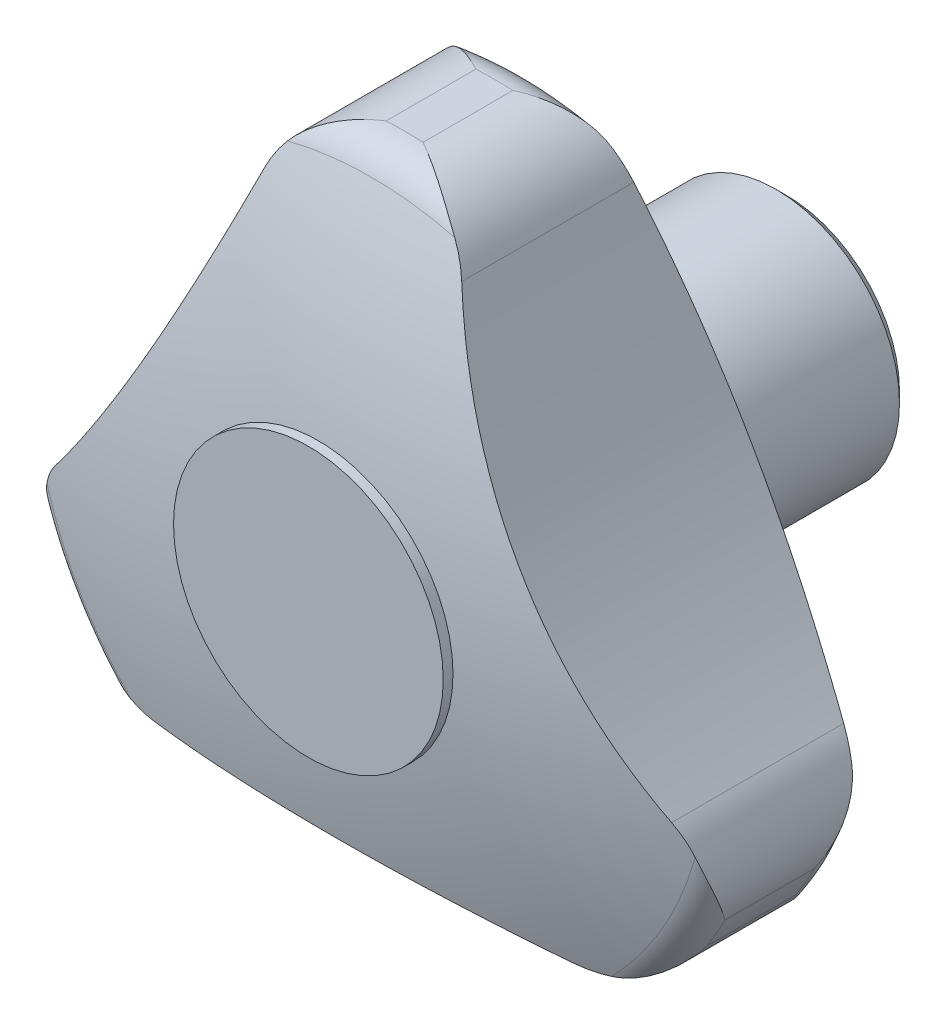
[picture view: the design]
ISO-10303-21;
HEADER;
FILE_DESCRIPTION(('STEP AP214'),'2;1');
FILE_NAME('part.step','',(''),(''),'','','');
FILE_SCHEMA(('AUTOMOTIVE_DESIGN { 1 0 10303 214 1 1 1 1 }'));
ENDSEC;
DATA;
#1=APPLICATION_CONTEXT('core data for automotive mechanical design processes');
#2=APPLICATION_PROTOCOL_DEFINITION('international standard','automotive_design',2000,#1);
#3=PRODUCT_CONTEXT('',#1,'mechanical');
#4=PRODUCT('Part','Part','',(#3));
#5=PRODUCT_RELATED_PRODUCT_CATEGORY('part','',(#4));
#6=PRODUCT_DEFINITION_FORMATION('','',#4);
#7=PRODUCT_DEFINITION_CONTEXT('part definition',#1,'design');
#8=PRODUCT_DEFINITION('design','',#6,#7);
#9=PRODUCT_DEFINITION_SHAPE('','',#8);
#10=(LENGTH_UNIT() NAMED_UNIT(*) SI_UNIT(.MILLI.,.METRE.));
#11=(NAMED_UNIT(*) PLANE_ANGLE_UNIT() SI_UNIT($,.RADIAN.));
#12=(NAMED_UNIT(*) SI_UNIT($,.STERADIAN.) SOLID_ANGLE_UNIT());
#13=UNCERTAINTY_MEASURE_WITH_UNIT(LENGTH_MEASURE(1.E-05),#10,'distance_accuracy_value','');
#14=(GEOMETRIC_REPRESENTATION_CONTEXT(3) GLOBAL_UNCERTAINTY_ASSIGNED_CONTEXT((#13)) GLOBAL_UNIT_ASSIGNED_CONTEXT((#10,
#11,#12)) REPRESENTATION_CONTEXT('',''));
#15=CARTESIAN_POINT('',(0.,0.,0.));
#16=DIRECTION('',(0.,0.,1.));
#17=DIRECTION('',(1.,0.,0.));
#18=AXIS2_PLACEMENT_3D('',#15,#16,#17);
#19=CARTESIAN_POINT('',(0.,2.77555756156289E-13,-50.4999999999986));
#20=DIRECTION('',(0.,0.,1.));
#21=DIRECTION('',(0.,-1.,0.));
#22=AXIS2_PLACEMENT_3D('',#19,#20,#21);
#23=SPHERICAL_SURFACE('',#22,103.999999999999);
#24=CARTESIAN_POINT('',(9.30341411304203,36.2662225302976,46.5268395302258));
#25=CARTESIAN_POINT('',(9.48514389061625,36.0425927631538,46.5930047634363));
#26=CARTESIAN_POINT('',(9.65680365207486,35.8115267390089,46.6615574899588));
#27=CARTESIAN_POINT('',(9.97797395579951,35.3380282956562,46.80236289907));
#28=CARTESIAN_POINT('',(10.1276303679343,35.095686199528,46.8745865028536));
#29=CARTESIAN_POINT('',(10.405333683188,34.5999848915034,47.0225936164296));
#30=CARTESIAN_POINT('',(10.5333813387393,34.346626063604,47.0983770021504));
#31=CARTESIAN_POINT('',(10.7680546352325,33.8289090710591,47.2534728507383));
#32=CARTESIAN_POINT('',(10.8745238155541,33.5644862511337,47.3328063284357));
#33=CARTESIAN_POINT('',(10.9693896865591,33.2963396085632,47.413360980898));
#34=B_SPLINE_CURVE_WITH_KNOTS('',3,(#24,#25,#26,#27,#28,#29,#30,#31,#32,#33),.UNSPECIFIED.,.F.,
.F.,(4,2,2,2,4),(0.,0.88665818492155,1.76714402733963,2.64759920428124,3.53422637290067),.UNSPECIFIED.);
#35=CARTESIAN_POINT('',(9.30396328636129,36.2655465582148,46.5270395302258));
#36=VERTEX_POINT('',#35);
#37=CARTESIAN_POINT('',(10.9693189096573,33.2965396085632,47.4133008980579));
#38=VERTEX_POINT('',#37);
#39=EDGE_CURVE('E332',#36,#38,#34,.T.);
#40=ORIENTED_EDGE('',*,*,#39,.F.);
#41=CARTESIAN_POINT('',(0.,0.,46.5270395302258));
#42=DIRECTION('',(0.,0.,1.));
#43=DIRECTION('',(1.,0.,0.));
#44=AXIS2_PLACEMENT_3D('',#41,#42,#43);
#45=CIRCLE('',#44,37.44);
#46=CARTESIAN_POINT('',(-9.30396328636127,36.2655465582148,46.5270395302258));
#47=VERTEX_POINT('',#46);
#48=EDGE_CURVE('E172',#36,#47,#45,.T.);
#49=ORIENTED_EDGE('',*,*,#48,.T.);
#50=CARTESIAN_POINT('',(-10.969389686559,33.2963396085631,47.413360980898));
#51=CARTESIAN_POINT('',(-10.8745238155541,33.5644862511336,47.3328063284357));
#52=CARTESIAN_POINT('',(-10.7680546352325,33.8289090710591,47.2534728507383));
#53=CARTESIAN_POINT('',(-10.5333813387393,34.3466260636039,47.0983770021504));
#54=CARTESIAN_POINT('',(-10.405333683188,34.5999848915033,47.0225936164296));
#55=CARTESIAN_POINT('',(-10.1276303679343,35.0956861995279,46.8745865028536));
#56=CARTESIAN_POINT('',(-9.97797395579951,35.3380282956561,46.80236289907));
#57=CARTESIAN_POINT('',(-9.65680365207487,35.8115267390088,46.6615574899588));
#58=CARTESIAN_POINT('',(-9.48514389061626,36.0425927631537,46.5930047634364));
#59=CARTESIAN_POINT('',(-9.30341411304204,36.2662225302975,46.5268395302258));
#60=B_SPLINE_CURVE_WITH_KNOTS('',3,(#50,#51,#52,#53,#54,#55,#56,#57,#58,#59),.UNSPECIFIED.,.F.,
.F.,(4,2,2,2,4),(0.,0.886627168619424,1.76708234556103,2.64756818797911,3.53422637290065),.UNSPECIFIED.);
#61=CARTESIAN_POINT('',(-10.9693189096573,33.2965396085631,47.4133008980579));
#62=VERTEX_POINT('',#61);
#63=EDGE_CURVE('E323',#62,#47,#60,.T.);
#64=ORIENTED_EDGE('',*,*,#63,.F.);
#65=CARTESIAN_POINT('',(-10.9692481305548,33.2967396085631,47.4132408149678));
#66=CARTESIAN_POINT('',(-11.2987102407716,32.365714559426,47.6929493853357));
#67=CARTESIAN_POINT('',(-11.6406264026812,31.4338839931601,47.9553752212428));
#68=CARTESIAN_POINT('',(-12.349297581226,29.5703975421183,48.4451343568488));
#69=CARTESIAN_POINT('',(-12.7160537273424,28.6387416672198,48.672466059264));
#70=CARTESIAN_POINT('',(-13.474371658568,26.7773132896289,49.0915207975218));
#71=CARTESIAN_POINT('',(-13.8659377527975,25.8475411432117,49.2832376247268));
#72=CARTESIAN_POINT('',(-14.6735500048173,23.9919094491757,49.630560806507));
#73=CARTESIAN_POINT('',(-15.0895956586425,23.0660498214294,49.7861679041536));
#74=CARTESIAN_POINT('',(-15.9340357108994,21.2453954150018,50.0571314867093));
#75=CARTESIAN_POINT('',(-16.3617783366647,20.3504451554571,50.1734749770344));
#76=CARTESIAN_POINT('',(-17.2395590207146,18.5676638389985,50.3713858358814));
#77=CARTESIAN_POINT('',(-17.6895970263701,17.6798327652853,50.4529532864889));
#78=CARTESIAN_POINT('',(-18.6112868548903,15.9130800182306,50.5811082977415));
#79=CARTESIAN_POINT('',(-19.0829350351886,15.0341568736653,50.6277017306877));
#80=CARTESIAN_POINT('',(-20.047131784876,13.2867499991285,50.6858274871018));
#81=CARTESIAN_POINT('',(-20.5396801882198,12.4182661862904,50.6973600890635));
#82=CARTESIAN_POINT('',(-22.0055533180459,9.90270393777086,50.6797950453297));
#83=CARTESIAN_POINT('',(-23.0058802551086,8.2713575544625,50.6037870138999));
#84=CARTESIAN_POINT('',(-25.073415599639,5.06278721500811,50.323382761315));
#85=CARTESIAN_POINT('',(-26.1406307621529,3.48556875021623,50.1189735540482));
#86=CARTESIAN_POINT('',(-27.7997976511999,1.14667523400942,49.7138854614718));
#87=CARTESIAN_POINT('',(-28.3704410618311,0.361452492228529,49.5597486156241));
#88=CARTESIAN_POINT('',(-29.5259023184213,-1.19127140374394,49.2184404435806));
#89=CARTESIAN_POINT('',(-30.1107204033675,-1.95877225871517,49.0312685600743));
#90=CARTESIAN_POINT('',(-31.2931215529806,-3.47489219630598,48.6243215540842));
#91=CARTESIAN_POINT('',(-31.8907031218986,-4.2235134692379,48.404550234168));
#92=CARTESIAN_POINT('',(-33.0973270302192,-5.70109012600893,47.9328719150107));
#93=CARTESIAN_POINT('',(-33.7063689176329,-6.43004628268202,47.680966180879));
#94=CARTESIAN_POINT('',(-34.3204794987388,-7.1487609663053,47.4132263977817));
#95=B_SPLINE_CURVE_WITH_KNOTS('',3,(#65,#66,#67,#68,#69,#70,#71,#72,#73,#74,#75,#76,#77,#78,#79,
#80,#81,#82,#83,#84,#85,#86,#87,#88,#89,#90,#91,#92,#93,#94),.UNSPECIFIED.,.F.,.F.,(4,2,2,2,2,2,
2,2,2,2,2,2,2,2,4),(0.,3.07914254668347,6.15842519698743,9.23824414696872,12.3179997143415,
15.313276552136,18.3085463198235,21.3033130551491,24.2980560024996,30.0367874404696,
35.7760993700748,38.7239181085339,41.6717865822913,44.6193114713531,47.5667203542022),.UNSPECIFIED.);
#96=CARTESIAN_POINT('',(-34.3203086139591,-7.14856096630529,47.4133008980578));
#97=VERTEX_POINT('',#96);
#98=EDGE_CURVE('E331',#62,#97,#95,.T.);
#99=ORIENTED_EDGE('',*,*,#98,.T.);
#100=CARTESIAN_POINT('',(-36.059177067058,-10.0761183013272,46.5268395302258));
#101=CARTESIAN_POINT('',(-35.9563713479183,-9.80691675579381,46.5930057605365));
#102=CARTESIAN_POINT('',(-35.8420902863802,-9.54271812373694,46.6615595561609));
#103=CARTESIAN_POINT('',(-35.592609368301,-9.02781990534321,46.8023671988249));
#104=CARTESIAN_POINT('',(-35.4575606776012,-8.77703914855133,46.8745919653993));
#105=CARTESIAN_POINT('',(-35.16711687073,-8.28868390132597,47.0226014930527));
#106=CARTESIAN_POINT('',(-35.0117224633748,-8.0511089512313,47.098386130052));
#107=CARTESIAN_POINT('',(-34.6806963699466,-7.58901182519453,47.2534845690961));
#108=CARTESIAN_POINT('',(-34.5049304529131,-7.36459282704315,47.3328193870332));
#109=CARTESIAN_POINT('',(-34.3201377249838,-7.14836096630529,47.413375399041));
#110=B_SPLINE_CURVE_WITH_KNOTS('',3,(#100,#101,#102,#103,#104,#105,#106,#107,#108,#109),
.UNSPECIFIED.,.F.,.F.,(4,2,2,2,4),(0.,0.886671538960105,1.76717046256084,2.64763871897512,
3.53427923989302),.UNSPECIFIED.);
#111=CARTESIAN_POINT('',(-36.0588662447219,-10.0753047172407,46.5270395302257));
#112=VERTEX_POINT('',#111);
#113=EDGE_CURVE('E22',#112,#97,#110,.T.);
#114=ORIENTED_EDGE('',*,*,#113,.F.);
#115=CARTESIAN_POINT('',(-26.7549029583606,-26.190241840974,46.5270395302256));
#116=VERTEX_POINT('',#115);
#117=EDGE_CURVE('E680',#112,#116,#45,.T.);
#118=ORIENTED_EDGE('',*,*,#117,.T.);
#119=CARTESIAN_POINT('',(-22.8551626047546,-26.0429179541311,47.5581866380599));
#120=CARTESIAN_POINT('',(-22.9372116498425,-26.0624877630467,47.5338653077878));
#121=CARTESIAN_POINT('',(-23.0195259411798,-26.081024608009,47.5096387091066));
#122=CARTESIAN_POINT('',(-23.1847449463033,-26.1160390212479,47.4613588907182));
#123=CARTESIAN_POINT('',(-23.2676502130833,-26.1325142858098,47.4373058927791));
#124=CARTESIAN_POINT('',(-23.6290737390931,-26.1995795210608,47.3332019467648));
#125=CARTESIAN_POINT('',(-23.9099819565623,-26.2394758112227,47.2542286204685));
#126=CARTESIAN_POINT('',(-24.4751156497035,-26.2952916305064,47.0992472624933));
#127=CARTESIAN_POINT('',(-24.7593430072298,-26.3111968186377,47.0232410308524));
#128=CARTESIAN_POINT('',(-25.3294885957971,-26.3186693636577,46.8746967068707));
#129=CARTESIAN_POINT('',(-25.6154086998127,-26.3102008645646,46.8021638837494));
#130=CARTESIAN_POINT('',(-26.1866152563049,-26.2686407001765,46.6612407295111));
#131=CARTESIAN_POINT('',(-26.4719013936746,-26.2355387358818,46.5928521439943));
#132=CARTESIAN_POINT('',(-27.0261408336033,-26.1468279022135,46.4639625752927));
#133=CARTESIAN_POINT('',(-27.2952262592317,-26.0923628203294,46.403241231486));
#134=CARTESIAN_POINT('',(-27.8288539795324,-25.9612040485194,46.2866189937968));
#135=CARTESIAN_POINT('',(-28.0933984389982,-25.8845212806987,46.2307157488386));
#136=CARTESIAN_POINT('',(-28.6159621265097,-25.7092780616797,46.1242125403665));
#137=CARTESIAN_POINT('',(-28.8739870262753,-25.6107374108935,46.0736078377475));
#138=CARTESIAN_POINT('',(-29.381855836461,-25.3921965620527,45.9780886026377));
#139=CARTESIAN_POINT('',(-29.6317008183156,-25.2721991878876,45.9331733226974));
#140=CARTESIAN_POINT('',(-30.0781266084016,-25.0344106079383,45.8568263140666));
#141=CARTESIAN_POINT('',(-30.2763293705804,-24.9199635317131,45.8244136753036));
#142=CARTESIAN_POINT('',(-30.6648659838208,-24.6774247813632,45.7639291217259));
#143=CARTESIAN_POINT('',(-30.8552010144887,-24.5493351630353,45.7358565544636));
#144=CARTESIAN_POINT('',(-31.227189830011,-24.2799107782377,45.6842086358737));
#145=CARTESIAN_POINT('',(-31.4088347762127,-24.1385629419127,45.6606377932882));
#146=CARTESIAN_POINT('',(-31.7623103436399,-23.8433545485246,45.6181754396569));
#147=CARTESIAN_POINT('',(-31.9341385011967,-23.689490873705,45.5992850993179));
#148=CARTESIAN_POINT('',(-32.100547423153,-23.5297170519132,45.5828146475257));
#149=B_SPLINE_CURVE_WITH_KNOTS('',3,(#119,#120,#121,#122,#123,#124,#125,#126,#127,#128,#129,
#130,#131,#132,#133,#134,#135,#136,#137,#138,#139,#140,#141,#142,#143,#144,#145,#146,#147,#148),
.UNSPECIFIED.,.F.,.F.,(4,2,2,2,2,2,2,2,2,2,2,2,2,2,4),(0.,0.263337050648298,0.526965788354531,
1.40938240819,2.29232629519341,3.17656973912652,4.06118308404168,4.90377649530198,
5.74595639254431,6.58737647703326,7.42868590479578,8.12160209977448,8.81441402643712,
9.50791624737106,10.2015917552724),.UNSPECIFIED.);
#150=CARTESIAN_POINT('',(-23.3509897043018,-26.1479786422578,47.4133008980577));
#151=VERTEX_POINT('',#150);
#152=EDGE_CURVE('E144',#151,#116,#149,.T.);
#153=ORIENTED_EDGE('',*,*,#152,.F.);
#154=CARTESIAN_POINT('',(-23.3511897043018,-26.1480157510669,47.4132432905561));
#155=CARTESIAN_POINT('',(-22.380167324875,-25.9678258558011,47.6929517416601));
#156=CARTESIAN_POINT('',(-21.4022203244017,-25.7980187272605,47.9553774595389));
#157=CARTESIAN_POINT('',(-19.4340581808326,-25.4800028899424,48.4451363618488));
#158=CARTESIAN_POINT('',(-18.4438424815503,-25.3317951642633,48.672467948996));
#159=CARTESIAN_POINT('',(-16.4526393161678,-25.0578037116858,49.0915224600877));
#160=CARTESIAN_POINT('',(-15.4516500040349,-24.9320238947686,49.2832391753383));
#161=CARTESIAN_POINT('',(-13.4408197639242,-24.7036209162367,49.6305621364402));
#162=CARTESIAN_POINT('',(-12.4309790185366,-24.6009972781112,49.786169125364));
#163=CARTESIAN_POINT('',(-10.4320260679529,-24.421976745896,50.0571325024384));
#164=CARTESIAN_POINT('',(-9.44310509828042,-24.344937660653,50.1734758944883));
#165=CARTESIAN_POINT('',(-7.46028085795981,-24.213727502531,50.3713865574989));
#166=CARTESIAN_POINT('',(-6.4663775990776,-24.159556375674,50.4529539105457));
#167=CARTESIAN_POINT('',(-4.47547994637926,-24.074386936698,50.581108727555));
#168=CARTESIAN_POINT('',(-3.47848609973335,-24.0433847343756,50.6277020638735));
#169=CARTESIAN_POINT('',(-1.4830890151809,-24.0047003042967,50.6858276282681));
#170=CARTESIAN_POINT('',(-0.484685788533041,-23.9970178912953,50.6973601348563));
#171=CARTESIAN_POINT('',(2.4267859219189,-24.0087202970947,50.6797948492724));
#172=CARTESIAN_POINT('',(4.3397311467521,-24.0593554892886,50.6037870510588));
#173=CARTESIAN_POINT('',(8.15219102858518,-24.2456076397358,50.3233840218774));
#174=CARTESIAN_POINT('',(10.0517043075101,-24.3812331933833,50.1189758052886));
#175=CARTESIAN_POINT('',(12.906820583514,-24.6486657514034,49.7138897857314));
#176=CARTESIAN_POINT('',(13.8721622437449,-24.7502455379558,49.5597537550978));
#177=CARTESIAN_POINT('',(15.7945855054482,-24.9745412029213,49.2184474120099));
#178=CARTESIAN_POINT('',(16.7516669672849,-25.0972574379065,49.031276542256));
#179=CARTESIAN_POINT('',(18.6558603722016,-25.3631854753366,48.6243317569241));
#180=CARTESIAN_POINT('',(19.6029734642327,-25.5063948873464,48.4045616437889));
#181=CARTESIAN_POINT('',(21.485898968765,-25.8125718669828,47.9328859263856));
#182=CARTESIAN_POINT('',(22.4217118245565,-25.9755386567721,47.6809815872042));
#183=CARTESIAN_POINT('',(23.3511897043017,-26.1480157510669,47.4132432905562));
#184=B_SPLINE_CURVE_WITH_KNOTS('',3,(#154,#155,#156,#157,#158,#159,#160,#161,#162,#163,#164,
#165,#166,#167,#168,#169,#170,#171,#172,#173,#174,#175,#176,#177,#178,#179,#180,#181,#182,#183),
.UNSPECIFIED.,.F.,.F.,(4,2,2,2,2,2,2,2,2,2,2,2,2,2,4),(0.,3.07914235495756,6.15842481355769,
9.2382435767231,12.3179989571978,15.3132757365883,18.3085454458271,21.3033121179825,
24.2980550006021,30.0367695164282,35.7760645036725,38.723874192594,41.6717336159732,
44.6192494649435,47.5666493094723),.UNSPECIFIED.);
#185=CARTESIAN_POINT('',(23.3509897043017,-26.1479786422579,47.4133008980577));
#186=VERTEX_POINT('',#185);
#187=EDGE_CURVE('E206',#151,#186,#184,.T.);
#188=ORIENTED_EDGE('',*,*,#187,.T.);
#189=CARTESIAN_POINT('',(32.100547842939,-23.529716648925,45.5828146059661));
#190=CARTESIAN_POINT('',(31.904118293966,-23.7183328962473,45.60225297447));
#191=CARTESIAN_POINT('',(31.7001269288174,-23.8986968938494,45.6250691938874));
#192=CARTESIAN_POINT('',(31.2786731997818,-24.241842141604,45.6771908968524));
#193=CARTESIAN_POINT('',(31.0612126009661,-24.4046256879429,45.706495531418));
#194=CARTESIAN_POINT('',(30.6152304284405,-24.7110254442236,45.7712153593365));
#195=CARTESIAN_POINT('',(30.3867517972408,-24.8547089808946,45.8066080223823));
#196=CARTESIAN_POINT('',(29.9196974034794,-25.1227772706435,45.8832543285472));
#197=CARTESIAN_POINT('',(29.6811223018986,-25.2471632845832,45.9245075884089));
#198=CARTESIAN_POINT('',(29.2248404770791,-25.4622009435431,46.007213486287));
#199=CARTESIAN_POINT('',(29.0080806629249,-25.5551111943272,46.0480438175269));
#200=CARTESIAN_POINT('',(28.5691888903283,-25.725189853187,46.133706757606));
#201=CARTESIAN_POINT('',(28.3470558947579,-25.8023551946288,46.1785401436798));
#202=CARTESIAN_POINT('',(27.8984015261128,-25.9407469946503,46.2719700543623));
#203=CARTESIAN_POINT('',(27.6718759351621,-26.0019572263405,46.3205703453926));
#204=CARTESIAN_POINT('',(27.2158058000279,-26.1081902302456,46.4212034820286));
#205=CARTESIAN_POINT('',(26.9862610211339,-26.1532117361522,46.4732365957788));
#206=CARTESIAN_POINT('',(26.4720061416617,-26.2355210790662,46.5928279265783));
#207=CARTESIAN_POINT('',(26.1868046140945,-26.2686183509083,46.6611953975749));
#208=CARTESIAN_POINT('',(25.6157180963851,-26.3101869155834,46.8020861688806));
#209=CARTESIAN_POINT('',(25.3298332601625,-26.3186633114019,46.8746086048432));
#210=CARTESIAN_POINT('',(24.7596553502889,-26.3112114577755,47.0231579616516));
#211=CARTESIAN_POINT('',(24.4753608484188,-26.2953106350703,47.0991808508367));
#212=CARTESIAN_POINT('',(23.9101003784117,-26.2394927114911,47.2541953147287));
#213=CARTESIAN_POINT('',(23.6291324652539,-26.1995904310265,47.3331850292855));
#214=CARTESIAN_POINT('',(23.2676464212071,-26.1325135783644,47.4373069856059));
#215=CARTESIAN_POINT('',(23.1847373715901,-26.1160375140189,47.461361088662));
#216=CARTESIAN_POINT('',(23.0195186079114,-26.0810229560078,47.5096408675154));
#217=CARTESIAN_POINT('',(22.9372082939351,-26.0624869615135,47.5338663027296));
#218=CARTESIAN_POINT('',(22.855163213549,-26.0429180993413,47.5581864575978));
#219=B_SPLINE_CURVE_WITH_KNOTS('',3,(#189,#190,#191,#192,#193,#194,#195,#196,#197,#198,#199,
#200,#201,#202,#203,#204,#205,#206,#207,#208,#209,#210,#211,#212,#213,#214,#215,#216,#217,#218),
.UNSPECIFIED.,.F.,.F.,(4,2,2,2,2,2,2,2,2,2,2,2,2,2,4),(0.,0.818776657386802,1.63744624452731,
2.45314887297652,3.26879818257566,3.9862201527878,4.70378172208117,5.42207025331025,
6.14041495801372,7.0247399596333,7.90888166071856,8.79202934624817,9.67463226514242,
9.93827305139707,10.2015974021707),.UNSPECIFIED.);
#220=CARTESIAN_POINT('',(26.7549029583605,-26.190241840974,46.5270395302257));
#221=VERTEX_POINT('',#220);
#222=EDGE_CURVE('E468',#221,#186,#219,.T.);
#223=ORIENTED_EDGE('',*,*,#222,.F.);
#224=CARTESIAN_POINT('',(36.0588662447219,-10.0753047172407,46.5270395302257));
#225=VERTEX_POINT('',#224);
#226=EDGE_CURVE('E503',#221,#225,#45,.T.);
#227=ORIENTED_EDGE('',*,*,#226,.T.);
#228=CARTESIAN_POINT('',(34.3201377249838,-7.14836096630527,47.413375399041));
#229=CARTESIAN_POINT('',(34.5049304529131,-7.36459282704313,47.3328193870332));
#230=CARTESIAN_POINT('',(34.6806963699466,-7.5890118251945,47.2534845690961));
#231=CARTESIAN_POINT('',(35.0117224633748,-8.05110895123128,47.098386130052));
#232=CARTESIAN_POINT('',(35.16711687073,-8.28868390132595,47.0226014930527));
#233=CARTESIAN_POINT('',(35.4575606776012,-8.77703914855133,46.8745919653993));
#234=CARTESIAN_POINT('',(35.5926093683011,-9.02781990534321,46.8023671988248));
#235=CARTESIAN_POINT('',(35.8420902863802,-9.54271812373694,46.6615595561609));
#236=CARTESIAN_POINT('',(35.9563713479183,-9.80691675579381,46.5930057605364));
#237=CARTESIAN_POINT('',(36.0591770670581,-10.0761183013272,46.5268395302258));
#238=B_SPLINE_CURVE_WITH_KNOTS('',3,(#228,#229,#230,#231,#232,#233,#234,#235,#236,#237),
.UNSPECIFIED.,.F.,.F.,(4,2,2,2,4),(0.,0.88664052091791,1.76710877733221,2.64760770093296,
3.53427923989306),.UNSPECIFIED.);
#239=CARTESIAN_POINT('',(34.3203086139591,-7.14856096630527,47.4133008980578));
#240=VERTEX_POINT('',#239);
#241=EDGE_CURVE('E425',#240,#225,#238,.T.);
#242=ORIENTED_EDGE('',*,*,#241,.F.);
#243=CARTESIAN_POINT('',(34.3204794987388,-7.14876096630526,47.4132263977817));
#244=CARTESIAN_POINT('',(33.6789190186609,-6.39792626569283,47.6929355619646));
#245=CARTESIAN_POINT('',(33.042887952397,-5.63590327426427,47.9553619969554));
#246=CARTESIAN_POINT('',(31.7833964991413,-4.09043353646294,48.4451223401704));
#247=CARTESIAN_POINT('',(31.1599366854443,-3.30698581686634,48.6724546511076));
#248=CARTESIAN_POINT('',(29.9270508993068,-1.7195497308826,49.0915106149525));
#249=CARTESIAN_POINT('',(29.3176273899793,-0.915557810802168,49.2832280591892));
#250=CARTESIAN_POINT('',(28.1144087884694,0.711670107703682,49.6305524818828));
#251=CARTESIAN_POINT('',(27.5206133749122,1.53490570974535,49.7861602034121));
#252=CARTESIAN_POINT('',(26.366099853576,3.1765388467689,50.0571250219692));
#253=CARTESIAN_POINT('',(25.8049212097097,3.99444966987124,50.1734691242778));
#254=CARTESIAN_POINT('',(24.6998770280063,5.64602014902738,50.3713812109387));
#255=CARTESIAN_POINT('',(24.1560114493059,6.47967976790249,50.452949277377));
#256=CARTESIAN_POINT('',(23.0868029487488,8.16126244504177,50.5811055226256));
#257=CARTESIAN_POINT('',(22.5614569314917,9.00918308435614,50.6276995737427));
#258=CARTESIAN_POINT('',(21.5302558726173,10.7179049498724,50.6858265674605));
#259=CARTESIAN_POINT('',(21.0244006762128,11.5787060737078,50.6973597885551));
#260=CARTESIAN_POINT('',(19.5787953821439,14.1059699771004,50.6797965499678));
#261=CARTESIAN_POINT('',(18.6661707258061,15.7879513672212,50.6037897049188));
#262=CARTESIAN_POINT('',(16.9212335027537,19.1827740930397,50.3233878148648));
#263=CARTESIAN_POINT('',(16.0889290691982,20.8956185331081,50.1189797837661));
#264=CARTESIAN_POINT('',(14.8929701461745,23.5019456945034,49.7138934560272));
#265=CARTESIAN_POINT('',(14.4982686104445,24.3887486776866,49.5597572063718));
#266=CARTESIAN_POINT('',(13.7313000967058,26.1657693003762,49.2184502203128));
#267=CARTESIAN_POINT('',(13.3590334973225,27.0559869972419,49.0312789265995));
#268=CARTESIAN_POINT('',(12.6372348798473,28.8380363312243,48.6243330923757));
#269=CARTESIAN_POINT('',(12.2877002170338,29.7298677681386,48.4045623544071));
#270=CARTESIAN_POINT('',(11.6113924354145,31.5136230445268,47.9328851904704));
#271=CARTESIAN_POINT('',(11.2846184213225,32.4055468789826,47.680980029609));
#272=CARTESIAN_POINT('',(10.9692481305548,33.2967396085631,47.4132408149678));
#273=B_SPLINE_CURVE_WITH_KNOTS('',3,(#243,#244,#245,#246,#247,#248,#249,#250,#251,#252,#253,
#254,#255,#256,#257,#258,#259,#260,#261,#262,#263,#264,#265,#266,#267,#268,#269,#270,#271,#272),
.UNSPECIFIED.,.F.,.F.,(4,2,2,2,2,2,2,2,2,2,2,2,2,2,4),(0.,3.07914255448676,6.15842521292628,
9.2382441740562,12.3179997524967,15.313276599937,18.3085463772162,21.3033131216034,
24.2980560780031,30.03678749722,35.7760994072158,38.7239181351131,41.6717865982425,
44.6193114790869,47.5667203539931),.UNSPECIFIED.);
#274=EDGE_CURVE('E499',#240,#38,#273,.T.);
#275=ORIENTED_EDGE('',*,*,#274,.T.);
#276=EDGE_LOOP('',(#40,#49,#64,#99,#114,#118,#153,#188,#223,#227,#242,#275));
#277=FACE_BOUND('',#276,.T.);
#278=CARTESIAN_POINT('',(0.,0.,52.4125842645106));
#279=DIRECTION('',(0.,0.,-1.));
#280=DIRECTION('',(-1.,0.,0.));
#281=AXIS2_PLACEMENT_3D('',#278,#279,#280);
#282=CIRCLE('',#281,15.);
#283=CARTESIAN_POINT('',(-15.,0.,52.4125842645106));
#284=VERTEX_POINT('',#283);
#285=EDGE_CURVE('E9',#284,#284,#282,.T.);
#286=ORIENTED_EDGE('',*,*,#285,.T.);
#287=EDGE_LOOP('',(#286));
#288=FACE_BOUND('',#287,.T.);
#289=ADVANCED_FACE('F14',(#277,#288),#23,.T.);
#290=CARTESIAN_POINT('',(0.,0.,32.8123490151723));
#291=DIRECTION('',(0.,0.,1.));
#292=DIRECTION('',(1.,0.,0.));
#293=AXIS2_PLACEMENT_3D('',#290,#291,#292);
#294=TOROIDAL_SURFACE('',#293,36.,4.);
#295=CARTESIAN_POINT('',(-35.9801575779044,-9.87575602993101,29.0332519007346));
#296=CARTESIAN_POINT('',(-36.0259792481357,-9.98837235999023,29.0589236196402));
#297=CARTESIAN_POINT('',(-36.06958909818,-10.101437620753,29.0864524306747));
#298=CARTESIAN_POINT('',(-36.152409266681,-10.3282719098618,29.144911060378));
#299=CARTESIAN_POINT('',(-36.1916204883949,-10.4420407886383,29.1758401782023));
#300=CARTESIAN_POINT('',(-36.3026076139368,-10.7838378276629,29.2731775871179));
#301=CARTESIAN_POINT('',(-36.3678748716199,-11.0126968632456,29.3442151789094));
#302=CARTESIAN_POINT('',(-36.4811001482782,-11.4701431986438,29.4961478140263));
#303=CARTESIAN_POINT('',(-36.52913454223,-11.6987271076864,29.5769971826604));
#304=CARTESIAN_POINT('',(-36.6087997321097,-12.1557063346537,29.7471258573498));
#305=CARTESIAN_POINT('',(-36.6404226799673,-12.3841015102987,29.8364091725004));
#306=CARTESIAN_POINT('',(-36.6949009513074,-12.9088851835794,30.0501050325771));
#307=CARTESIAN_POINT('',(-36.712183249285,-13.2048737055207,30.1769557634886));
#308=CARTESIAN_POINT('',(-36.7207591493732,-13.7930340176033,30.4398055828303));
#309=CARTESIAN_POINT('',(-36.7120475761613,-14.0852050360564,30.575806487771));
#310=CARTESIAN_POINT('',(-36.6483307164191,-14.9549307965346,30.9948167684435));
#311=CARTESIAN_POINT('',(-36.5556828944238,-15.5250711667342,31.2885714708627));
#312=CARTESIAN_POINT('',(-36.3250543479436,-16.4441043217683,31.7873414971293));
#313=CARTESIAN_POINT('',(-36.213283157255,-16.8021802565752,31.9884816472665));
#314=CARTESIAN_POINT('',(-35.9512754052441,-17.501600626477,32.3935479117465));
#315=CARTESIAN_POINT('',(-35.8011186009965,-17.8429780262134,32.5974674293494));
#316=CARTESIAN_POINT('',(-35.6295101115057,-18.1806942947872,32.8049530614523));
#317=CARTESIAN_POINT('',(-35.6264454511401,-18.1867102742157,32.8086510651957));
#318=CARTESIAN_POINT('',(-35.6233747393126,-18.1927230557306,32.8123490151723));
#319=B_SPLINE_CURVE_WITH_KNOTS('',3,(#295,#296,#297,#298,#299,#300,#301,#302,#303,#304,#305,
#306,#307,#308,#309,#310,#311,#312,#313,#314,#315,#316,#317,#318),.UNSPECIFIED.,.F.,.F.,(4,2,2,
2,2,2,2,2,2,2,2,4),(0.,0.372708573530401,0.745340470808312,1.48948087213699,2.23028131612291,
2.97143569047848,3.93750896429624,4.90377459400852,6.83832849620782,8.1135947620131,
9.38623253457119,9.40932655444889),.UNSPECIFIED.);
#320=CARTESIAN_POINT('',(-35.9805145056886,-9.87663337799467,29.0334519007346));
#321=VERTEX_POINT('',#320);
#322=CARTESIAN_POINT('',(-35.6233750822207,-18.1927223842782,32.8123490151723));
#323=VERTEX_POINT('',#322);
#324=EDGE_CURVE('E451',#321,#323,#319,.T.);
#325=ORIENTED_EDGE('',*,*,#324,.F.);
#326=CARTESIAN_POINT('',(0.,0.,29.0334519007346));
#327=DIRECTION('',(0.,0.,1.));
#328=DIRECTION('',(1.,0.,0.));
#329=AXIS2_PLACEMENT_3D('',#326,#327,#328);
#330=CIRCLE('',#329,37.3114635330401);
#331=CARTESIAN_POINT('',(-26.543672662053,-26.2217229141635,29.0334519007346));
#332=VERTEX_POINT('',#331);
#333=EDGE_CURVE('E184',#321,#332,#330,.T.);
#334=ORIENTED_EDGE('',*,*,#333,.T.);
#335=CARTESIAN_POINT('',(-33.5670476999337,-21.7543859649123,32.8123490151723));
#336=CARTESIAN_POINT('',(-33.5633758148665,-21.7600516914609,32.8086510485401));
#337=CARTESIAN_POINT('',(-33.559698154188,-21.7657137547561,32.8049530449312));
#338=CARTESIAN_POINT('',(-33.3941011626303,-22.0200995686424,32.6386996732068));
#339=CARTESIAN_POINT('',(-33.2210387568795,-22.2617307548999,32.4760920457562));
#340=CARTESIAN_POINT('',(-32.8535263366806,-22.7292991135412,32.1524040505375));
#341=CARTESIAN_POINT('',(-32.6590693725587,-22.9552311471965,31.9913241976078));
#342=CARTESIAN_POINT('',(-32.2489294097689,-23.3906218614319,31.6718216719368));
#343=CARTESIAN_POINT('',(-32.0331867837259,-23.6000311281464,31.5134080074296));
#344=CARTESIAN_POINT('',(-31.5817563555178,-24.0000629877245,31.2015149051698));
#345=CARTESIAN_POINT('',(-31.3460747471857,-24.1906913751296,31.0480339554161));
#346=CARTESIAN_POINT('',(-30.8870681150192,-24.5283371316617,30.7672718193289));
#347=CARTESIAN_POINT('',(-30.6660547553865,-24.6778099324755,30.639160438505));
#348=CARTESIAN_POINT('',(-30.2099438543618,-24.9601026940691,30.3896783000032));
#349=CARTESIAN_POINT('',(-29.9748446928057,-25.0929207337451,30.2683083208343));
#350=CARTESIAN_POINT('',(-29.491946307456,-25.3401902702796,30.0344946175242));
#351=CARTESIAN_POINT('',(-29.2441865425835,-25.4546947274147,29.9220256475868));
#352=CARTESIAN_POINT('',(-28.7362449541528,-25.6643187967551,29.7078552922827));
#353=CARTESIAN_POINT('',(-28.4760697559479,-25.7594486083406,29.6061482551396));
#354=CARTESIAN_POINT('',(-27.942860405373,-25.9292819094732,29.4156317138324));
#355=CARTESIAN_POINT('',(-27.6697667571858,-26.0038773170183,29.3268915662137));
#356=CARTESIAN_POINT('',(-27.1133213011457,-26.1303372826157,29.1663059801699));
#357=CARTESIAN_POINT('',(-26.8299682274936,-26.1821990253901,29.0944626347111));
#358=CARTESIAN_POINT('',(-26.3790130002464,-26.2444546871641,28.9983621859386));
#359=CARTESIAN_POINT('',(-26.2140307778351,-26.2630905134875,28.9669269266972));
#360=CARTESIAN_POINT('',(-25.8820635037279,-26.2921715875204,28.9119066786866));
#361=CARTESIAN_POINT('',(-25.7150790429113,-26.3026191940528,28.888319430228));
#362=CARTESIAN_POINT('',(-25.3796701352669,-26.3151099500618,28.8500320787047));
#363=CARTESIAN_POINT('',(-25.2112449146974,-26.317148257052,28.8353371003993));
#364=CARTESIAN_POINT('',(-24.8739298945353,-26.3126697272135,28.8160357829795));
#365=CARTESIAN_POINT('',(-24.7050401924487,-26.3061545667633,28.8114274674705));
#366=CARTESIAN_POINT('',(-24.3928363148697,-26.2861702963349,28.8134170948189));
#367=CARTESIAN_POINT('',(-24.2494370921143,-26.2738733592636,28.8184571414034));
#368=CARTESIAN_POINT('',(-23.963912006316,-26.2431847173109,28.8376195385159));
#369=CARTESIAN_POINT('',(-23.8217858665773,-26.2247943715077,28.8517398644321));
#370=CARTESIAN_POINT('',(-23.5401123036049,-26.1822196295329,28.8898518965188));
#371=CARTESIAN_POINT('',(-23.40055914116,-26.1580504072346,28.9138178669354));
#372=CARTESIAN_POINT('',(-23.1248223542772,-26.1043186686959,28.9724114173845));
#373=CARTESIAN_POINT('',(-22.9886366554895,-26.0747595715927,29.0070322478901));
#374=CARTESIAN_POINT('',(-22.7731138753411,-26.0233443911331,29.0718991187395));
#375=CARTESIAN_POINT('',(-22.6923318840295,-26.0029838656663,29.0985799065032));
#376=CARTESIAN_POINT('',(-22.5327547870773,-25.9606773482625,29.1562957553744));
#377=CARTESIAN_POINT('',(-22.4539598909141,-25.9387311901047,29.187331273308));
#378=CARTESIAN_POINT('',(-22.3763053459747,-25.9160867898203,29.2206084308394));
#379=B_SPLINE_CURVE_WITH_KNOTS('',3,(#335,#336,#337,#338,#339,#340,#341,#342,#343,#344,#345,
#346,#347,#348,#349,#350,#351,#352,#353,#354,#355,#356,#357,#358,#359,#360,#361,#362,#363,#364,
#365,#366,#367,#368,#369,#370,#371,#372,#373,#374,#375,#376,#377,#378),.UNSPECIFIED.,.F.,.F.,(4,
2,2,2,2,2,2,2,2,2,2,2,2,2,2,2,2,2,2,2,2,4),(0.,0.0230940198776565,1.0382441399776,
2.05372499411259,3.07213595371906,4.0902317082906,4.97733649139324,5.86454350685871,
6.74913655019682,7.63326270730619,8.52195712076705,9.41076155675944,9.91737422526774,
10.4238408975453,10.9305991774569,11.4372581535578,11.8689156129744,12.3004768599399,
12.7309171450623,13.1610853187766,13.42338163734,13.6857054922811),.UNSPECIFIED.);
#380=CARTESIAN_POINT('',(-33.5670473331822,-21.7543865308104,32.8123490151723));
#381=VERTEX_POINT('',#380);
#382=EDGE_CURVE('E149',#381,#332,#379,.T.);
#383=ORIENTED_EDGE('',*,*,#382,.F.);
#384=CARTESIAN_POINT('',(0.,0.,32.8123490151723));
#385=DIRECTION('',(0.,0.,1.));
#386=DIRECTION('',(1.,0.,0.));
#387=AXIS2_PLACEMENT_3D('',#384,#385,#386);
#388=CIRCLE('',#387,40.);
#389=EDGE_CURVE('E159',#323,#381,#388,.T.);
#390=ORIENTED_EDGE('',*,*,#389,.F.);
#391=EDGE_LOOP('',(#325,#334,#383,#390));
#392=FACE_BOUND('',#391,.T.);
#393=ADVANCED_FACE('F253',(#392),#294,.T.);
#394=CARTESIAN_POINT('',(35.6233747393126,-18.1927230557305,32.8123490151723));
#395=CARTESIAN_POINT('',(35.6264454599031,-18.1867102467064,32.8086510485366));
#396=CARTESIAN_POINT('',(35.629510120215,-18.1806942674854,32.8049530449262));
#397=CARTESIAN_POINT('',(35.7670038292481,-17.9101145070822,32.6387146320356));
#398=CARTESIAN_POINT('',(35.8897211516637,-17.6394479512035,32.4761219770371));
#399=CARTESIAN_POINT('',(36.1108751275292,-17.0874414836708,32.1524635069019));
#400=CARTESIAN_POINT('',(36.2093038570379,-16.8060981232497,31.9913982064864));
#401=CARTESIAN_POINT('',(36.3813024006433,-16.2332150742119,31.6718948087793));
#402=CARTESIAN_POINT('',(36.454795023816,-15.9416467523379,31.5134662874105));
#403=CARTESIAN_POINT('',(36.5755335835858,-15.3506279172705,31.201543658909));
#404=CARTESIAN_POINT('',(36.6227875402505,-15.0511798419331,31.0480480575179));
#405=CARTESIAN_POINT('',(36.6857091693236,-14.4847081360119,30.7672178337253));
#406=CARTESIAN_POINT('',(36.7046531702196,-14.2184574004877,30.6390545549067));
#407=CARTESIAN_POINT('',(36.721059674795,-13.6820870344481,30.3894768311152));
#408=CARTESIAN_POINT('',(36.7185199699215,-13.4119670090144,30.2680630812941));
#409=CARTESIAN_POINT('',(36.6911754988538,-12.8701303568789,30.0342656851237));
#410=CARTESIAN_POINT('',(36.6664547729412,-12.5984235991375,29.9218496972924));
#411=CARTESIAN_POINT('',(36.5940398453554,-12.0539536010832,29.7077785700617));
#412=CARTESIAN_POINT('',(36.5463567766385,-11.7811909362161,29.6061182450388));
#413=CARTESIAN_POINT('',(36.4269011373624,-11.2348495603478,29.4157240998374));
#414=CARTESIAN_POINT('',(36.3550208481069,-10.9612727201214,29.3270506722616));
#415=CARTESIAN_POINT('',(36.2286187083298,-10.5526796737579,29.2066636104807));
#416=CARTESIAN_POINT('',(36.1833254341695,-10.4166232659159,29.1686022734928));
#417=CARTESIAN_POINT('',(36.0864624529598,-10.1454185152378,29.0972287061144));
#418=CARTESIAN_POINT('',(36.034889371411,-10.0102707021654,29.0639190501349));
#419=CARTESIAN_POINT('',(35.9801575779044,-9.875756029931,29.0332519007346));
#420=B_SPLINE_CURVE_WITH_KNOTS('',3,(#394,#395,#396,#397,#398,#399,#400,#401,#402,#403,#404,
#405,#406,#407,#408,#409,#410,#411,#412,#413,#414,#415,#416,#417,#418,#419),.UNSPECIFIED.,.F.,
.F.,(4,2,2,2,2,2,2,2,2,2,2,2,4),(0.,0.0230940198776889,1.03815072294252,2.05353814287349,
3.07204066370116,4.09023169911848,4.9777024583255,5.86526445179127,6.74947775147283,
7.63326278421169,8.52103536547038,8.96593722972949,9.4110792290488),.UNSPECIFIED.);
#421=CARTESIAN_POINT('',(35.6233747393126,-18.1927230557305,32.8123490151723));
#422=VERTEX_POINT('',#421);
#423=CARTESIAN_POINT('',(35.9805145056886,-9.87663337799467,29.0334519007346));
#424=VERTEX_POINT('',#423);
#425=EDGE_CURVE('E272',#422,#424,#420,.T.);
#426=ORIENTED_EDGE('',*,*,#425,.F.);
#427=CARTESIAN_POINT('',(33.5670481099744,-21.754385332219,32.8123490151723));
#428=VERTEX_POINT('',#427);
#429=EDGE_CURVE('E170',#428,#422,#388,.T.);
#430=ORIENTED_EDGE('',*,*,#429,.F.);
#431=CARTESIAN_POINT('',(22.3763053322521,-25.9160867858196,29.2206084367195));
#432=CARTESIAN_POINT('',(22.4953111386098,-25.950811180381,29.1695962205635));
#433=CARTESIAN_POINT('',(22.6170011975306,-25.9838621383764,29.1238708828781));
#434=CARTESIAN_POINT('',(22.8645397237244,-26.0459780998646,29.0425260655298));
#435=CARTESIAN_POINT('',(22.9903830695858,-26.0750478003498,29.0068946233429));
#436=CARTESIAN_POINT('',(23.2445678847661,-26.1284923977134,28.945329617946));
#437=CARTESIAN_POINT('',(23.3728906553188,-26.1528935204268,28.9193410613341));
#438=CARTESIAN_POINT('',(23.6318560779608,-26.196835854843,28.8761393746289));
#439=CARTESIAN_POINT('',(23.7624995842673,-26.2163752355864,28.8589295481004));
#440=CARTESIAN_POINT('',(24.0613158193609,-26.2549823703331,28.8290343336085));
#441=CARTESIAN_POINT('',(24.2299518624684,-26.2724501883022,28.8188853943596));
#442=CARTESIAN_POINT('',(24.5682646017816,-26.2987925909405,28.8104153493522));
#443=CARTESIAN_POINT('',(24.7379419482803,-26.307661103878,28.8121025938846));
#444=CARTESIAN_POINT('',(25.0772391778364,-26.3167504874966,28.8260025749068));
#445=CARTESIAN_POINT('',(25.2468588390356,-26.3169628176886,28.8382256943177));
#446=CARTESIAN_POINT('',(25.5848713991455,-26.3088274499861,28.8719762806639));
#447=CARTESIAN_POINT('',(25.7532648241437,-26.300483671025,28.8934994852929));
#448=CARTESIAN_POINT('',(26.0252624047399,-26.2801530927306,28.935117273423));
#449=CARTESIAN_POINT('',(26.1294557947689,-26.2707100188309,28.9527145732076));
#450=CARTESIAN_POINT('',(26.3368413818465,-26.248646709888,28.9908404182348));
#451=CARTESIAN_POINT('',(26.4400345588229,-26.2360300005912,29.0113656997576));
#452=CARTESIAN_POINT('',(26.7821614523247,-26.1888000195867,29.0842758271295));
#453=CARTESIAN_POINT('',(27.0189071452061,-26.1472644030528,29.142696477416));
#454=CARTESIAN_POINT('',(27.4856965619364,-26.0481591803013,29.2718014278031));
#455=CARTESIAN_POINT('',(27.7157349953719,-25.9905772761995,29.3424951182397));
#456=CARTESIAN_POINT('',(28.1689303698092,-25.8601017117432,29.4943362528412));
#457=CARTESIAN_POINT('',(28.3920571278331,-25.7871494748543,29.5755232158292));
#458=CARTESIAN_POINT('',(28.82972278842,-25.6270409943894,29.7463615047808));
#459=CARTESIAN_POINT('',(29.0442626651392,-25.5398863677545,29.8360118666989));
#460=CARTESIAN_POINT('',(29.5272056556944,-25.324124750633,30.0502528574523));
#461=CARTESIAN_POINT('',(29.79249658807,-25.1909205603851,30.1772664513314));
#462=CARTESIAN_POINT('',(30.3067796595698,-24.9038412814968,30.4404831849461));
#463=CARTESIAN_POINT('',(30.5557657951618,-24.7499586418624,30.5766896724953));
#464=CARTESIAN_POINT('',(31.2766851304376,-24.2599648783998,30.9955852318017));
#465=CARTESIAN_POINT('',(31.7234830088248,-23.8950958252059,31.2889639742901));
#466=CARTESIAN_POINT('',(32.4034827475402,-23.2364223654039,31.7873000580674));
#467=CARTESIAN_POINT('',(32.6576509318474,-22.9606475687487,31.9883981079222));
#468=CARTESIAN_POINT('',(33.1323769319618,-22.3840423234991,32.3934632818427));
#469=CARTESIAN_POINT('',(33.3529894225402,-22.0832538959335,32.5974251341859));
#470=CARTESIAN_POINT('',(33.5596981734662,-21.7657137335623,32.804953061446));
#471=CARTESIAN_POINT('',(33.5633758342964,-21.7600516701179,32.8086510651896));
#472=CARTESIAN_POINT('',(33.5670476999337,-21.7543859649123,32.8123490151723));
#473=B_SPLINE_CURVE_WITH_KNOTS('',3,(#431,#432,#433,#434,#435,#436,#437,#438,#439,#440,#441,
#442,#443,#444,#445,#446,#447,#448,#449,#450,#451,#452,#453,#454,#455,#456,#457,#458,#459,#460,
#461,#462,#463,#464,#465,#466,#467,#468,#469,#470,#471,#472),.UNSPECIFIED.,.F.,.F.,(4,2,2,2,2,2,
2,2,2,2,2,2,2,2,2,2,2,2,2,2,4),(0.,0.401930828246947,0.803383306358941,1.20250976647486,
1.60178631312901,2.11059926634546,2.61977121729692,3.1294455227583,3.63888648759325,
3.95706854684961,4.27489867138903,5.0158651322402,5.75740103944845,6.50181579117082,
7.24614585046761,8.21340216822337,9.18101265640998,11.1130444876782,12.3880466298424,
13.6609485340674,13.6840425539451),.UNSPECIFIED.);
#474=CARTESIAN_POINT('',(26.5436726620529,-26.2217229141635,29.0334519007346));
#475=VERTEX_POINT('',#474);
#476=EDGE_CURVE('E263',#475,#428,#473,.T.);
#477=ORIENTED_EDGE('',*,*,#476,.F.);
#478=EDGE_CURVE('E179',#475,#424,#330,.T.);
#479=ORIENTED_EDGE('',*,*,#478,.T.);
#480=EDGE_LOOP('',(#426,#430,#477,#479));
#481=FACE_BOUND('',#480,.T.);
#482=ADVANCED_FACE('F254',(#481),#294,.T.);
#483=CARTESIAN_POINT('',(0.,0.,53.5));
#484=DIRECTION('',(0.,0.,1.));
#485=DIRECTION('',(1.,0.,0.));
#486=AXIS2_PLACEMENT_3D('',#483,#484,#485);
#487=CYLINDRICAL_SURFACE('',#486,40.);
#488=DIRECTION('',(0.,0.,-1.));
#489=VECTOR('',#488,1.);
#490=CARTESIAN_POINT('',(35.6233747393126,-18.1927230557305,53.5));
#491=LINE('',#490,#489);
#492=CARTESIAN_POINT('',(35.6233747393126,-18.1927230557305,42.7952303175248));
#493=VERTEX_POINT('',#492);
#494=EDGE_CURVE('E438',#493,#422,#491,.T.);
#495=ORIENTED_EDGE('',*,*,#494,.F.);
#496=CARTESIAN_POINT('',(0.,0.,42.7952303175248));
#497=DIRECTION('',(0.,0.,1.));
#498=DIRECTION('',(1.,0.,0.));
#499=AXIS2_PLACEMENT_3D('',#496,#497,#498);
#500=CIRCLE('',#499,40.);
#501=CARTESIAN_POINT('',(33.5670481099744,-21.754385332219,42.7952303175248));
#502=VERTEX_POINT('',#501);
#503=EDGE_CURVE('E167',#502,#493,#500,.T.);
#504=ORIENTED_EDGE('',*,*,#503,.F.);
#505=DIRECTION('',(0.,0.,-1.));
#506=VECTOR('',#505,1.);
#507=CARTESIAN_POINT('',(33.5670481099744,-21.754385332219,53.5));
#508=LINE('',#507,#506);
#509=EDGE_CURVE('E472',#502,#428,#508,.T.);
#510=ORIENTED_EDGE('',*,*,#509,.T.);
#511=ORIENTED_EDGE('',*,*,#429,.T.);
#512=EDGE_LOOP('',(#495,#504,#510,#511));
#513=FACE_BOUND('',#512,.T.);
#514=ADVANCED_FACE('F521',(#513),#487,.T.);
#515=CARTESIAN_POINT('',(-35.6233750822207,-18.1927223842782,42.7952303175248));
#516=VERTEX_POINT('',#515);
#517=CARTESIAN_POINT('',(-33.5670473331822,-21.7543865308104,42.7952303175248));
#518=VERTEX_POINT('',#517);
#519=EDGE_CURVE('E157',#516,#518,#500,.T.);
#520=ORIENTED_EDGE('',*,*,#519,.F.);
#521=DIRECTION('',(0.,0.,-1.));
#522=VECTOR('',#521,1.);
#523=CARTESIAN_POINT('',(-35.6233750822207,-18.1927223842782,53.5));
#524=LINE('',#523,#522);
#525=EDGE_CURVE('E161',#516,#323,#524,.T.);
#526=ORIENTED_EDGE('',*,*,#525,.T.);
#527=ORIENTED_EDGE('',*,*,#389,.T.);
#528=DIRECTION('',(0.,0.,-1.));
#529=VECTOR('',#528,1.);
#530=CARTESIAN_POINT('',(-33.5670473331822,-21.7543865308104,53.5));
#531=LINE('',#530,#529);
#532=EDGE_CURVE('E141',#518,#381,#531,.T.);
#533=ORIENTED_EDGE('',*,*,#532,.F.);
#534=EDGE_LOOP('',(#520,#526,#527,#533));
#535=FACE_BOUND('',#534,.T.);
#536=ADVANCED_FACE('F155',(#535),#487,.T.);
#537=CARTESIAN_POINT('',(0.,0.,42.7952303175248));
#538=DIRECTION('',(0.,0.,1.));
#539=DIRECTION('',(1.,0.,0.));
#540=AXIS2_PLACEMENT_3D('',#537,#538,#539);
#541=TOROIDAL_SURFACE('',#540,36.,4.);
#542=CARTESIAN_POINT('',(-35.6233747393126,-18.1927230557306,42.7952303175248));
#543=CARTESIAN_POINT('',(-35.6264454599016,-18.186710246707,42.798928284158));
#544=CARTESIAN_POINT('',(-35.6295101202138,-18.1806942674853,42.8026262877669));
#545=CARTESIAN_POINT('',(-35.7670125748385,-17.910097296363,42.968875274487));
#546=CARTESIAN_POINT('',(-35.8897371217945,-17.6394127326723,43.1314785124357));
#547=CARTESIAN_POINT('',(-36.1109023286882,-17.0873689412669,43.4551578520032));
#548=CARTESIAN_POINT('',(-36.2093350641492,-16.8060062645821,43.6162334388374));
#549=CARTESIAN_POINT('',(-36.3813273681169,-16.2331197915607,43.9357365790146));
#550=CARTESIAN_POINT('',(-36.4548129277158,-15.9415685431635,44.0941549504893));
#551=CARTESIAN_POINT('',(-36.5755400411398,-15.350586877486,44.4060567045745));
#552=CARTESIAN_POINT('',(-36.6227898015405,-15.0511589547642,44.5595416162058));
#553=CARTESIAN_POINT('',(-36.6857010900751,-14.4847813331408,44.8403252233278));
#554=CARTESIAN_POINT('',(-36.7046427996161,-14.2186053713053,44.9684535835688));
#555=CARTESIAN_POINT('',(-36.7210566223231,-13.6823777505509,45.2179695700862));
#556=CARTESIAN_POINT('',(-36.7185259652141,-13.4123255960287,45.3393563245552));
#557=CARTESIAN_POINT('',(-36.6912051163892,-12.8704786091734,45.5731685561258));
#558=CARTESIAN_POINT('',(-36.6664864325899,-12.5986921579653,45.6856215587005));
#559=CARTESIAN_POINT('',(-36.594058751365,-12.054065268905,45.8997593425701));
#560=CARTESIAN_POINT('',(-36.546363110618,-11.7812255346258,46.0014503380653));
#561=CARTESIAN_POINT('',(-36.4342155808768,-11.2682978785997,46.1801976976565));
#562=CARTESIAN_POINT('',(-36.3724140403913,-11.0281544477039,46.258745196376));
#563=CARTESIAN_POINT('',(-36.2298322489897,-10.5496211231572,46.4031747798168));
#564=CARTESIAN_POINT('',(-36.1490465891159,-10.3112317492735,46.4690532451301));
#565=CARTESIAN_POINT('',(-35.9411267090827,-9.76727770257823,46.6027466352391));
#566=CARTESIAN_POINT('',(-35.8073541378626,-9.46284068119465,46.6653003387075));
#567=CARTESIAN_POINT('',(-35.5826487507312,-9.01444702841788,46.7339343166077));
#568=CARTESIAN_POINT('',(-35.5036879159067,-8.86627829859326,46.752616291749));
#569=CARTESIAN_POINT('',(-35.3379670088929,-8.5734140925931,46.7804312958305));
#570=CARTESIAN_POINT('',(-35.2512082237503,-8.42871804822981,46.7895658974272));
#571=CARTESIAN_POINT('',(-35.0823225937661,-8.16259802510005,46.7965555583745));
#572=CARTESIAN_POINT('',(-35.0011054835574,-8.04063107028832,46.7957449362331));
#573=CARTESIAN_POINT('',(-34.8335861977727,-7.80065241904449,46.7851486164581));
#574=CARTESIAN_POINT('',(-34.7472850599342,-7.68263992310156,46.77536474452));
#575=CARTESIAN_POINT('',(-34.5704327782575,-7.45155892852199,46.7459719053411));
#576=CARTESIAN_POINT('',(-34.4798929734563,-7.33847864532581,46.7263879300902));
#577=CARTESIAN_POINT('',(-34.295256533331,-7.11776842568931,46.6765554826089));
#578=CARTESIAN_POINT('',(-34.201161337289,-7.01013632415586,46.6463112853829));
#579=CARTESIAN_POINT('',(-33.9987108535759,-6.78818564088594,46.5699048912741));
#580=CARTESIAN_POINT('',(-33.8900241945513,-6.67467087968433,46.522243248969));
#581=CARTESIAN_POINT('',(-33.7260278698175,-6.51103118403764,46.4391661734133));
#582=CARTESIAN_POINT('',(-33.6711249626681,-6.45752080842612,46.4094940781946));
#583=CARTESIAN_POINT('',(-33.5613084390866,-6.35287096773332,46.3462005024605));
#584=CARTESIAN_POINT('',(-33.5063948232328,-6.30173207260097,46.3125780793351));
#585=CARTESIAN_POINT('',(-33.4516203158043,-6.25184036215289,46.2769414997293));
#586=B_SPLINE_CURVE_WITH_KNOTS('',3,(#542,#543,#544,#545,#546,#547,#548,#549,#550,#551,#552,
#553,#554,#555,#556,#557,#558,#559,#560,#561,#562,#563,#564,#565,#566,#567,#568,#569,#570,#571,
#572,#573,#574,#575,#576,#577,#578,#579,#580,#581,#582,#583,#584,#585),.UNSPECIFIED.,.F.,.F.,(4,
2,2,2,2,2,2,2,2,2,2,2,2,2,2,2,2,2,2,2,2,4),(0.,0.0230940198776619,1.03821675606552,
2.05367020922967,3.07211033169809,4.09023170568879,4.97745675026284,5.86479626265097,
6.74928627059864,7.63326273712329,8.41264621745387,9.19225202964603,10.2039299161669,
10.7103398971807,11.2166664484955,11.6558962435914,12.0950366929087,12.5330629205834,
12.9709136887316,13.4625734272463,13.7090843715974,13.9556542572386),.UNSPECIFIED.);
#587=EDGE_CURVE('E165',#516,#112,#586,.T.);
#588=ORIENTED_EDGE('',*,*,#587,.F.);
#589=ORIENTED_EDGE('',*,*,#519,.T.);
#590=CARTESIAN_POINT('',(-22.3646195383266,-25.9126720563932,46.3819429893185));
#591=CARTESIAN_POINT('',(-22.4832182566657,-25.9474343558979,46.4331998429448));
#592=CARTESIAN_POINT('',(-22.6045101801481,-25.9805434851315,46.4791845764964));
#593=CARTESIAN_POINT('',(-22.8512736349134,-26.0428134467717,46.5610699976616));
#594=CARTESIAN_POINT('',(-22.976740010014,-26.0719789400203,46.5969826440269));
#595=CARTESIAN_POINT('',(-23.230152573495,-26.1256400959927,46.6591124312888));
#596=CARTESIAN_POINT('',(-23.3580787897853,-26.1501633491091,46.6853877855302));
#597=CARTESIAN_POINT('',(-23.6162751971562,-26.1943848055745,46.7291781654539));
#598=CARTESIAN_POINT('',(-23.7465462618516,-26.214081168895,46.746689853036));
#599=CARTESIAN_POINT('',(-24.0449031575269,-26.2531280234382,46.777319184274));
#600=CARTESIAN_POINT('',(-24.2134654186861,-26.2708705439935,46.7878749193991));
#601=CARTESIAN_POINT('',(-24.5516701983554,-26.2977691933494,46.7971173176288));
#602=CARTESIAN_POINT('',(-24.7213133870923,-26.3069193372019,46.7957957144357));
#603=CARTESIAN_POINT('',(-25.0606493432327,-26.3165750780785,46.7825852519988));
#604=CARTESIAN_POINT('',(-25.2303418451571,-26.3170685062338,46.7706815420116));
#605=CARTESIAN_POINT('',(-25.5685293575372,-26.3094854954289,46.7375262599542));
#606=CARTESIAN_POINT('',(-25.7370248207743,-26.3014124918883,46.7162784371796));
#607=CARTESIAN_POINT('',(-26.0478614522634,-26.2786834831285,46.6692246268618));
#608=CARTESIAN_POINT('',(-26.1904562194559,-26.2651502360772,46.6445244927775));
#609=CARTESIAN_POINT('',(-26.4737157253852,-26.2321593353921,46.5897627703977));
#610=CARTESIAN_POINT('',(-26.6143826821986,-26.2127092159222,46.5597080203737));
#611=CARTESIAN_POINT('',(-26.9971449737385,-26.151510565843,46.470722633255));
#612=CARTESIAN_POINT('',(-27.2371965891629,-26.1039164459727,46.4068922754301));
#613=CARTESIAN_POINT('',(-27.709940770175,-25.9922863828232,46.2671499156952));
#614=CARTESIAN_POINT('',(-27.9426280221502,-25.9282388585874,46.1912294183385));
#615=CARTESIAN_POINT('',(-28.4004817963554,-25.7844691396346,46.0291164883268));
#616=CARTESIAN_POINT('',(-28.6256163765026,-25.7046883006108,45.9428861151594));
#617=CARTESIAN_POINT('',(-29.066694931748,-25.5306229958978,45.7621598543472));
#618=CARTESIAN_POINT('',(-29.2826398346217,-25.4363399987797,45.6676648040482));
#619=CARTESIAN_POINT('',(-29.766442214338,-25.2046966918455,45.4432969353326));
#620=CARTESIAN_POINT('',(-30.0310759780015,-25.0627918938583,45.3111427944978));
#621=CARTESIAN_POINT('',(-30.5433202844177,-24.7581270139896,45.0380513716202));
#622=CARTESIAN_POINT('',(-30.7909245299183,-24.5953592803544,44.8971108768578));
#623=CARTESIAN_POINT('',(-31.2679740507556,-24.2508759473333,44.6087988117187));
#624=CARTESIAN_POINT('',(-31.4974414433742,-24.0691840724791,44.4614354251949));
#625=CARTESIAN_POINT('',(-31.9378851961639,-23.6881736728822,44.161917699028));
#626=CARTESIAN_POINT('',(-32.1488595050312,-23.4888531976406,44.0097628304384));
#627=CARTESIAN_POINT('',(-32.5760827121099,-23.0487928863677,43.6836028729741));
#628=CARTESIAN_POINT('',(-32.7898639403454,-22.8059621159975,43.5091871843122));
#629=CARTESIAN_POINT('',(-33.1921081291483,-22.301967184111,43.1585981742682));
#630=CARTESIAN_POINT('',(-33.3806066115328,-22.0408295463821,42.9824277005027));
#631=CARTESIAN_POINT('',(-33.5596981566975,-21.7657137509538,42.8026262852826));
#632=CARTESIAN_POINT('',(-33.5633758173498,-21.7600516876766,42.798928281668));
#633=CARTESIAN_POINT('',(-33.5670476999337,-21.7543859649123,42.7952303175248));
#634=B_SPLINE_CURVE_WITH_KNOTS('',3,(#590,#591,#592,#593,#594,#595,#596,#597,#598,#599,#600,
#601,#602,#603,#604,#605,#606,#607,#608,#609,#610,#611,#612,#613,#614,#615,#616,#617,#618,#619,
#620,#621,#622,#623,#624,#625,#626,#627,#628,#629,#630,#631,#632,#633),.UNSPECIFIED.,.F.,.F.,(4,
2,2,2,2,2,2,2,2,2,2,2,2,2,2,2,2,2,2,2,2,4),(0.,0.401158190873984,0.801838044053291,
1.20005612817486,1.59842577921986,2.10717502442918,2.61627837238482,3.12609731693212,
3.63571188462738,4.07151869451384,4.50677288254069,5.26440639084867,6.02257463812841,
6.7836241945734,7.54459673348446,8.52746376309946,9.51069230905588,10.4927027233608,
11.4748219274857,12.5761420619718,13.6758982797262,13.6989922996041),.UNSPECIFIED.);
#635=EDGE_CURVE('E138',#116,#518,#634,.T.);
#636=ORIENTED_EDGE('',*,*,#635,.F.);
#637=ORIENTED_EDGE('',*,*,#117,.F.);
#638=EDGE_LOOP('',(#588,#589,#636,#637));
#639=FACE_BOUND('',#638,.T.);
#640=ADVANCED_FACE('F164',(#639),#541,.T.);
#641=CARTESIAN_POINT('',(36.0585553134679,-10.0744910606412,46.5272395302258));
#642=CARTESIAN_POINT('',(36.1027472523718,-10.1901190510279,46.4988173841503));
#643=CARTESIAN_POINT('',(36.1446323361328,-10.3061497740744,46.4685603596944));
#644=CARTESIAN_POINT('',(36.2238240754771,-10.5388227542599,46.4046918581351));
#645=CARTESIAN_POINT('',(36.2611316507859,-10.6554648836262,46.3710810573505));
#646=CARTESIAN_POINT('',(36.3661632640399,-11.0057441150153,46.2657756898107));
#647=CARTESIAN_POINT('',(36.4271257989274,-11.24007491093,46.1895227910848));
#648=CARTESIAN_POINT('',(36.5311887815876,-11.7082017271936,46.0273374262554));
#649=CARTESIAN_POINT('',(36.5743582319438,-11.9419962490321,45.9414440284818));
#650=CARTESIAN_POINT('',(36.6437213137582,-12.4090241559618,45.7614171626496));
#651=CARTESIAN_POINT('',(36.6699070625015,-12.6422572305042,45.667279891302));
#652=CARTESIAN_POINT('',(36.7111035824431,-13.1758160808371,45.4434358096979));
#653=CARTESIAN_POINT('',(36.7205318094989,-13.475618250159,45.3114336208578));
#654=CARTESIAN_POINT('',(36.7128737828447,-14.0708724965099,45.0386842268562));
#655=CARTESIAN_POINT('',(36.6957820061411,-14.3663236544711,44.8979352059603));
#656=CARTESIAN_POINT('',(36.6360984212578,-14.9517066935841,44.60966603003));
#657=CARTESIAN_POINT('',(36.5934759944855,-15.2416315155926,44.4621379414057));
#658=CARTESIAN_POINT('',(36.4836614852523,-15.8142653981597,44.1622774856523));
#659=CARTESIAN_POINT('',(36.4164666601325,-16.0969736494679,44.009944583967));
#660=CARTESIAN_POINT('',(36.2488661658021,-16.687372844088,43.6835729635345));
#661=CARTESIAN_POINT('',(36.1454386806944,-16.9939803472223,43.5091267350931));
#662=CARTESIAN_POINT('',(35.9100784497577,-17.5943271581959,43.1585370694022));
#663=CARTESIAN_POINT('',(35.7781963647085,-17.8880882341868,42.9823971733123));
#664=CARTESIAN_POINT('',(35.6295101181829,-18.1806942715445,42.8026262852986));
#665=CARTESIAN_POINT('',(35.6264454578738,-18.1867102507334,42.7989282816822));
#666=CARTESIAN_POINT('',(35.6233747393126,-18.1927230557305,42.7952303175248));
#667=B_SPLINE_CURVE_WITH_KNOTS('',3,(#641,#642,#643,#644,#645,#646,#647,#648,#649,#650,#651,
#652,#653,#654,#655,#656,#657,#658,#659,#660,#661,#662,#663,#664,#665,#666),.UNSPECIFIED.,.F.,
.F.,(4,2,2,2,2,2,2,2,2,2,2,2,4),(0.,0.380939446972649,0.761802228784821,1.52240816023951,
2.28003601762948,3.03801526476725,4.01980078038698,5.00179078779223,5.98496084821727,
6.96824067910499,8.06975144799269,9.16931702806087,9.1924110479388),.UNSPECIFIED.);
#668=EDGE_CURVE('E405',#225,#493,#667,.T.);
#669=ORIENTED_EDGE('',*,*,#668,.F.);
#670=ORIENTED_EDGE('',*,*,#226,.F.);
#671=CARTESIAN_POINT('',(33.5670476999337,-21.7543859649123,42.7952303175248));
#672=CARTESIAN_POINT('',(33.5633758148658,-21.7600516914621,42.798928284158));
#673=CARTESIAN_POINT('',(33.5596981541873,-21.7657137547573,42.8026262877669));
#674=CARTESIAN_POINT('',(33.3941054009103,-22.0200930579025,42.9688754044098));
#675=CARTESIAN_POINT('',(33.2210478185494,-22.261718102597,43.1314787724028));
#676=CARTESIAN_POINT('',(32.8535461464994,-22.7292750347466,43.4551583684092));
#677=CARTESIAN_POINT('',(32.6590951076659,-22.9552017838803,43.6162340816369));
#678=CARTESIAN_POINT('',(32.2489569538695,-23.390594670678,43.9357372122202));
#679=CARTESIAN_POINT('',(32.0332090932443,-23.6000104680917,44.0941554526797));
#680=CARTESIAN_POINT('',(31.5817678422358,-24.0000536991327,44.4060569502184));
#681=CARTESIAN_POINT('',(31.3460807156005,-24.1906869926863,44.5595417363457));
#682=CARTESIAN_POINT('',(30.8870397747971,-24.5283579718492,44.8403248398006));
#683=CARTESIAN_POINT('',(30.665996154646,-24.6778495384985,44.9684528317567));
#684=CARTESIAN_POINT('',(30.2098177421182,-24.9601774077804,45.2179681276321));
#685=CARTESIAN_POINT('',(29.9746811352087,-25.0930115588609,45.3393545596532));
#686=CARTESIAN_POINT('',(29.4917676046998,-25.3402747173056,45.5731668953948));
#687=CARTESIAN_POINT('',(29.2440336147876,-25.4547613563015,45.6856202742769));
#688=CARTESIAN_POINT('',(28.7361576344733,-25.6643513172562,45.8997587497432));
#689=CARTESIAN_POINT('',(28.4760229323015,-25.7594658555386,46.0014500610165));
#690=CARTESIAN_POINT('',(27.9757385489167,-25.9188077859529,46.1801982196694));
#691=CARTESIAN_POINT('',(27.736865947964,-25.9853581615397,46.2587461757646));
#692=CARTESIAN_POINT('',(27.2511529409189,-26.1011451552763,46.4031756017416));
#693=CARTESIAN_POINT('',(27.0043103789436,-26.1503770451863,46.4690536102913));
#694=CARTESIAN_POINT('',(26.4292787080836,-26.2422891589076,46.602745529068));
#695=CARTESIAN_POINT('',(26.0987471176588,-26.278656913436,46.6652984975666));
#696=CARTESIAN_POINT('',(25.598075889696,-26.3082538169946,46.7339330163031));
#697=CARTESIAN_POINT('',(25.4302743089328,-26.3139563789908,46.7526155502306));
#698=CARTESIAN_POINT('',(25.093780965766,-26.3168701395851,46.7804311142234));
#699=CARTESIAN_POINT('',(24.9250893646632,-26.314082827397,46.7895658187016));
#700=CARTESIAN_POINT('',(24.6105777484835,-26.300900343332,46.7965467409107));
#701=CARTESIAN_POINT('',(24.4647419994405,-26.2915821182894,46.7957494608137));
#702=CARTESIAN_POINT('',(24.1739456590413,-26.2665984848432,46.7852306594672));
#703=CARTESIAN_POINT('',(24.0289848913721,-26.2509344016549,46.7755110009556));
#704=CARTESIAN_POINT('',(23.7412086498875,-26.2134872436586,46.7463068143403));
#705=CARTESIAN_POINT('',(23.5983886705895,-26.1917197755,46.7268470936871));
#706=CARTESIAN_POINT('',(23.3156632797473,-26.1424055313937,46.677324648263));
#707=CARTESIAN_POINT('',(23.1757563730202,-26.114861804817,46.6472675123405));
#708=CARTESIAN_POINT('',(22.9223219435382,-26.0594096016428,46.5815353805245));
#709=CARTESIAN_POINT('',(22.8081850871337,-26.0322793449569,46.5475531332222));
#710=CARTESIAN_POINT('',(22.5834887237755,-25.9747823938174,46.4711642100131));
#711=CARTESIAN_POINT('',(22.4729325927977,-25.9444127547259,46.4287498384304));
#712=CARTESIAN_POINT('',(22.3646195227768,-25.9126720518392,46.3819429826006));
#713=B_SPLINE_CURVE_WITH_KNOTS('',3,(#671,#672,#673,#674,#675,#676,#677,#678,#679,#680,#681,
#682,#683,#684,#685,#686,#687,#688,#689,#690,#691,#692,#693,#694,#695,#696,#697,#698,#699,#700,
#701,#702,#703,#704,#705,#706,#707,#708,#709,#710,#711,#712),.UNSPECIFIED.,.F.,.F.,(4,2,2,2,2,2,
2,2,2,2,2,2,2,2,2,2,2,2,2,2,4),(0.,0.0230940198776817,1.03821756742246,2.05367183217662,
3.07211114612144,4.09023170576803,4.97745414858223,5.86479107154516,6.7492836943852,
7.63326273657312,8.41265107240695,9.19225202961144,10.2039151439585,10.7103352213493,
11.216666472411,11.6546982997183,12.0926386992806,12.5294693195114,12.9660699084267,
13.3321165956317,13.6984989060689),.UNSPECIFIED.);
#714=EDGE_CURVE('E399',#502,#221,#713,.T.);
#715=ORIENTED_EDGE('',*,*,#714,.F.);
#716=ORIENTED_EDGE('',*,*,#503,.T.);
#717=EDGE_LOOP('',(#669,#670,#715,#716));
#718=FACE_BOUND('',#717,.T.);
#719=ADVANCED_FACE('F393',(#718),#541,.T.);
#720=CARTESIAN_POINT('',(0.,0.,0.));
#721=DIRECTION('',(0.,0.,1.));
#722=DIRECTION('',(1.,0.,0.));
#723=AXIS2_PLACEMENT_3D('',#720,#721,#722);
#724=PLANE('',#723);
#725=CARTESIAN_POINT('',(0.,0.,0.));
#726=DIRECTION('',(0.,0.,1.));
#727=DIRECTION('',(1.,0.,0.));
#728=AXIS2_PLACEMENT_3D('',#725,#726,#727);
#729=CIRCLE('',#728,9.375);
#730=CARTESIAN_POINT('',(9.375,0.,0.));
#731=VERTEX_POINT('',#730);
#732=EDGE_CURVE('E196',#731,#731,#729,.T.);
#733=ORIENTED_EDGE('',*,*,#732,.F.);
#734=EDGE_LOOP('',(#733));
#735=FACE_BOUND('',#734,.T.);
#736=CARTESIAN_POINT('',(0.,0.,0.));
#737=DIRECTION('',(0.,0.,-1.));
#738=DIRECTION('',(-1.,0.,0.));
#739=AXIS2_PLACEMENT_3D('',#736,#737,#738);
#740=CIRCLE('',#739,5.);
#741=CARTESIAN_POINT('',(-5.,0.,0.));
#742=VERTEX_POINT('',#741);
#743=EDGE_CURVE('E485',#742,#742,#740,.T.);
#744=ORIENTED_EDGE('',*,*,#743,.F.);
#745=EDGE_LOOP('',(#744));
#746=FACE_BOUND('',#745,.T.);
#747=ADVANCED_FACE('F16',(#735,#746),#724,.F.);
#748=CARTESIAN_POINT('',(0.,0.,53.5));
#749=DIRECTION('',(0.,0.,1.));
#750=DIRECTION('',(1.,0.,0.));
#751=AXIS2_PLACEMENT_3D('',#748,#749,#750);
#752=CYLINDRICAL_SURFACE('',#751,9.375);
#753=CARTESIAN_POINT('',(0.,0.,0.3));
#754=DIRECTION('',(0.,0.,1.));
#755=DIRECTION('',(1.,0.,0.));
#756=AXIS2_PLACEMENT_3D('',#753,#754,#755);
#757=CIRCLE('',#756,9.375);
#758=CARTESIAN_POINT('',(9.375,0.,0.3));
#759=VERTEX_POINT('',#758);
#760=EDGE_CURVE('E193',#759,#759,#757,.T.);
#761=ORIENTED_EDGE('',*,*,#760,.F.);
#762=EDGE_LOOP('',(#761));
#763=FACE_BOUND('',#762,.T.);
#764=ORIENTED_EDGE('',*,*,#732,.T.);
#765=EDGE_LOOP('',(#764));
#766=FACE_BOUND('',#765,.T.);
#767=ADVANCED_FACE('F616',(#763,#766),#752,.T.);
#768=CARTESIAN_POINT('',(0.,9.375,0.3));
#769=DIRECTION('',(0.,0.,1.));
#770=DIRECTION('',(1.,0.,0.));
#771=AXIS2_PLACEMENT_3D('',#768,#769,#770);
#772=PLANE('',#771);
#773=CARTESIAN_POINT('',(0.,0.,0.3));
#774=DIRECTION('',(0.,0.,1.));
#775=DIRECTION('',(1.,0.,0.));
#776=AXIS2_PLACEMENT_3D('',#773,#774,#775);
#777=CIRCLE('',#776,12.55);
#778=CARTESIAN_POINT('',(12.55,0.,0.3));
#779=VERTEX_POINT('',#778);
#780=EDGE_CURVE('E190',#779,#779,#777,.T.);
#781=ORIENTED_EDGE('',*,*,#780,.F.);
#782=EDGE_LOOP('',(#781));
#783=FACE_BOUND('',#782,.T.);
#784=ORIENTED_EDGE('',*,*,#760,.T.);
#785=EDGE_LOOP('',(#784));
#786=FACE_BOUND('',#785,.T.);
#787=ADVANCED_FACE('F606',(#783,#786),#772,.F.);
#788=CARTESIAN_POINT('',(0.,0.,0.3));
#789=DIRECTION('',(0.,0.,1.));
#790=DIRECTION('',(1.,0.,0.));
#791=AXIS2_PLACEMENT_3D('',#788,#789,#790);
#792=CONICAL_SURFACE('',#791,12.55,0.785398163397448);
#793=CARTESIAN_POINT('',(0.,0.,1.5));
#794=DIRECTION('',(0.,0.,1.));
#795=DIRECTION('',(1.,0.,0.));
#796=AXIS2_PLACEMENT_3D('',#793,#794,#795);
#797=CIRCLE('',#796,13.75);
#798=CARTESIAN_POINT('',(13.75,0.,1.5));
#799=VERTEX_POINT('',#798);
#800=EDGE_CURVE('E187',#799,#799,#797,.T.);
#801=ORIENTED_EDGE('',*,*,#800,.F.);
#802=EDGE_LOOP('',(#801));
#803=FACE_BOUND('',#802,.T.);
#804=ORIENTED_EDGE('',*,*,#780,.T.);
#805=EDGE_LOOP('',(#804));
#806=FACE_BOUND('',#805,.T.);
#807=ADVANCED_FACE('F597',(#803,#806),#792,.T.);
#808=CARTESIAN_POINT('',(0.,0.,53.5));
#809=DIRECTION('',(0.,0.,1.));
#810=DIRECTION('',(1.,0.,0.));
#811=AXIS2_PLACEMENT_3D('',#808,#809,#810);
#812=CYLINDRICAL_SURFACE('',#811,13.75);
#813=CARTESIAN_POINT('',(0.,0.,23.2706833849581));
#814=DIRECTION('',(0.,0.,1.));
#815=DIRECTION('',(1.,0.,0.));
#816=AXIS2_PLACEMENT_3D('',#813,#814,#815);
#817=CIRCLE('',#816,13.75);
#818=CARTESIAN_POINT('',(13.75,0.,23.2706833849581));
#819=VERTEX_POINT('',#818);
#820=EDGE_CURVE('E183',#819,#819,#817,.T.);
#821=ORIENTED_EDGE('',*,*,#820,.F.);
#822=EDGE_LOOP('',(#821));
#823=FACE_BOUND('',#822,.T.);
#824=ORIENTED_EDGE('',*,*,#800,.T.);
#825=EDGE_LOOP('',(#824));
#826=FACE_BOUND('',#825,.T.);
#827=ADVANCED_FACE('F588',(#823,#826),#812,.T.);
#828=CARTESIAN_POINT('',(0.,0.,150.884803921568));
#829=DIRECTION('',(0.,0.,1.));
#830=DIRECTION('',(1.,0.,0.));
#831=AXIS2_PLACEMENT_3D('',#828,#829,#830);
#832=DEGENERATE_TOROIDAL_SURFACE('',#831,4.97696078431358,128.980862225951,.F.);
#833=ORIENTED_EDGE('',*,*,#820,.T.);
#834=EDGE_LOOP('',(#833));
#835=FACE_BOUND('',#834,.T.);
#836=CARTESIAN_POINT('',(-34.3201377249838,-7.14836096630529,28.274158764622));
#837=CARTESIAN_POINT('',(-34.4935151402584,-7.35123894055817,28.3430841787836));
#838=CARTESIAN_POINT('',(-34.6589304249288,-7.56130200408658,28.4109225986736));
#839=CARTESIAN_POINT('',(-34.9717945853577,-7.99319664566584,28.5435968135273));
#840=CARTESIAN_POINT('',(-35.1193480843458,-8.21494755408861,28.6084485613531));
#841=CARTESIAN_POINT('',(-35.3966166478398,-8.67015867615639,28.7351836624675));
#842=CARTESIAN_POINT('',(-35.5263312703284,-8.9036191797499,28.7970669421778));
#843=CARTESIAN_POINT('',(-35.7677274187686,-9.38234121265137,28.9178353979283));
#844=CARTESIAN_POINT('',(-35.8792919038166,-9.62766704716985,28.9766995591));
#845=CARTESIAN_POINT('',(-35.9808712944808,-9.87751062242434,29.0336519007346));
#846=B_SPLINE_CURVE_WITH_KNOTS('',3,(#836,#837,#838,#839,#840,#841,#842,#843,#844,#845),
.UNSPECIFIED.,.F.,.F.,(4,2,2,2,4),(0.,0.826682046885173,1.64825995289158,2.4698582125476,
3.29656081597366),.UNSPECIFIED.);
#847=CARTESIAN_POINT('',(-34.3203086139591,-7.14856096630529,28.2742267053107));
#848=VERTEX_POINT('',#847);
#849=EDGE_CURVE('E453',#848,#321,#846,.T.);
#850=ORIENTED_EDGE('',*,*,#849,.F.);
#851=CARTESIAN_POINT('',(-34.3204794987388,-7.14876096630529,28.2742946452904));
#852=CARTESIAN_POINT('',(-33.625767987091,-6.33571809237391,27.9981102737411));
#853=CARTESIAN_POINT('',(-32.9383677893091,-5.51053885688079,27.7390915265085));
#854=CARTESIAN_POINT('',(-31.5796174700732,-3.83676305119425,27.2565216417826));
#855=CARTESIAN_POINT('',(-30.9082692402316,-2.98816374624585,27.032974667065));
#856=CARTESIAN_POINT('',(-29.5826829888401,-1.26790528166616,26.6223855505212));
#857=CARTESIAN_POINT('',(-28.9284591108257,-0.396228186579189,26.4353728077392));
#858=CARTESIAN_POINT('',(-27.6391842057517,1.36833822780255,26.099363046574));
#859=CARTESIAN_POINT('',(-27.0041324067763,2.26122669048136,25.9503644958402));
#860=CARTESIAN_POINT('',(-25.7715645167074,4.04243157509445,25.6951877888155));
#861=CARTESIAN_POINT('',(-25.1734975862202,4.93021601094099,25.5879585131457));
#862=CARTESIAN_POINT('',(-23.9981570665,6.72320996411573,25.4118346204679));
#863=CARTESIAN_POINT('',(-23.420883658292,7.62841963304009,25.3429403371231));
#864=CARTESIAN_POINT('',(-22.2886832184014,9.45416736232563,25.2443793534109));
#865=CARTESIAN_POINT('',(-21.7337448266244,10.3746972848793,25.2146924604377));
#866=CARTESIAN_POINT('',(-20.6470791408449,12.2297431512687,25.194899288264));
#867=CARTESIAN_POINT('',(-20.1153509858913,13.1642585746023,25.2047915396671));
#868=CARTESIAN_POINT('',(-19.1710317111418,14.8736264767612,25.2585981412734));
#869=CARTESIAN_POINT('',(-18.754417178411,15.646469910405,25.2959693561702));
#870=CARTESIAN_POINT('',(-17.9378376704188,17.199240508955,25.3967018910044));
#871=CARTESIAN_POINT('',(-17.5378738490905,17.9791681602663,25.4600650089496));
#872=CARTESIAN_POINT('',(-16.3634753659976,20.328283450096,25.6884402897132));
#873=CARTESIAN_POINT('',(-15.6145247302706,21.9068196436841,25.8917389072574));
#874=CARTESIAN_POINT('',(-14.5360557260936,24.3044645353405,26.2721916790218));
#875=CARTESIAN_POINT('',(-14.1803739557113,25.1178501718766,26.4136007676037));
#876=CARTESIAN_POINT('',(-13.4875722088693,26.7479376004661,26.7210737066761));
#877=CARTESIAN_POINT('',(-13.1504525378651,27.5646394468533,26.8871379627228));
#878=CARTESIAN_POINT('',(-12.4950733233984,29.1999125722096,27.2431643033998));
#879=CARTESIAN_POINT('',(-12.1768050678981,30.0184828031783,27.4331152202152));
#880=CARTESIAN_POINT('',(-11.5589890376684,31.6568866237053,27.8363506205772));
#881=CARTESIAN_POINT('',(-11.2594401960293,32.4767201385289,28.0496337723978));
#882=CARTESIAN_POINT('',(-10.9692481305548,33.2967396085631,28.2742814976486));
#883=B_SPLINE_CURVE_WITH_KNOTS('',3,(#851,#852,#853,#854,#855,#856,#857,#858,#859,#860,#861,
#862,#863,#864,#865,#866,#867,#868,#869,#870,#871,#872,#873,#874,#875,#876,#877,#878,#879,#880,
#881,#882),.UNSPECIFIED.,.F.,.F.,(4,2,2,2,2,2,2,2,2,2,2,2,2,2,2,4),(0.,3.31336721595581,
6.62712298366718,9.94353444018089,13.2598121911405,16.4862080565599,19.7126320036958,
22.9373936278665,26.1620355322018,28.7977837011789,31.4337142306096,36.7055198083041,
39.4019557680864,42.0984360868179,44.7936603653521,47.4887308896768),.UNSPECIFIED.);
#884=CARTESIAN_POINT('',(-10.9693189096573,33.2965396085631,28.2742267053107));
#885=VERTEX_POINT('',#884);
#886=EDGE_CURVE('E356',#848,#885,#883,.T.);
#887=ORIENTED_EDGE('',*,*,#886,.T.);
#888=CARTESIAN_POINT('',(-9.43626052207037,36.0991039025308,29.0336519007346));
#889=CARTESIAN_POINT('',(-9.60183905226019,35.8862151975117,28.9767004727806));
#890=CARTESIAN_POINT('',(-9.75851284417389,35.666938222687,28.9178372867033));
#891=CARTESIAN_POINT('',(-10.0523961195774,35.2185295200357,28.7970708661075));
#892=CARTESIAN_POINT('',(-10.1897198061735,34.989466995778,28.7351886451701));
#893=CARTESIAN_POINT('',(-10.4453070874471,34.5217478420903,28.6084557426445));
#894=CARTESIAN_POINT('',(-10.5635711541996,34.2830914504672,28.5436051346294));
#895=CARTESIAN_POINT('',(-10.7811692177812,33.7962043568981,28.4109332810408));
#896=CARTESIAN_POINT('',(-10.8803810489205,33.5479233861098,28.3430960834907));
#897=CARTESIAN_POINT('',(-10.969389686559,33.2963396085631,28.2741719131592));
#898=B_SPLINE_CURVE_WITH_KNOTS('',3,(#888,#889,#890,#891,#892,#893,#894,#895,#896,#897),
.UNSPECIFIED.,.F.,.F.,(4,2,2,2,4),(0.,0.826689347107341,1.64827459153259,2.46983948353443,
3.29650827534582),.UNSPECIFIED.);
#899=CARTESIAN_POINT('',(-9.43684184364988,36.0983562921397,29.0334519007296));
#900=VERTEX_POINT('',#899);
#901=EDGE_CURVE('E298',#900,#885,#898,.T.);
#902=ORIENTED_EDGE('',*,*,#901,.F.);
#903=CARTESIAN_POINT('',(9.43684184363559,36.0983562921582,29.0334519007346));
#904=VERTEX_POINT('',#903);
#905=EDGE_CURVE('E180',#904,#900,#330,.T.);
#906=ORIENTED_EDGE('',*,*,#905,.F.);
#907=CARTESIAN_POINT('',(10.9693896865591,33.2963396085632,28.2741719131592));
#908=CARTESIAN_POINT('',(10.8803810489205,33.5479233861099,28.3430960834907));
#909=CARTESIAN_POINT('',(10.7811692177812,33.7962043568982,28.4109332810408));
#910=CARTESIAN_POINT('',(10.5635711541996,34.2830914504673,28.5436051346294));
#911=CARTESIAN_POINT('',(10.4453070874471,34.5217478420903,28.6084557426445));
#912=CARTESIAN_POINT('',(10.1897198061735,34.9894669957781,28.7351886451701));
#913=CARTESIAN_POINT('',(10.0523961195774,35.2185295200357,28.7970708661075));
#914=CARTESIAN_POINT('',(9.75851284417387,35.6669382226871,28.9178372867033));
#915=CARTESIAN_POINT('',(9.60183905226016,35.8862151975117,28.9767004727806));
#916=CARTESIAN_POINT('',(9.43626052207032,36.0991039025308,29.0336519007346));
#917=B_SPLINE_CURVE_WITH_KNOTS('',3,(#907,#908,#909,#910,#911,#912,#913,#914,#915,#916),
.UNSPECIFIED.,.F.,.F.,(4,2,2,2,4),(0.,0.826668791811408,1.64823368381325,2.4698189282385,
3.29650827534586),.UNSPECIFIED.);
#918=CARTESIAN_POINT('',(10.9693189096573,33.2965396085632,28.2742267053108));
#919=VERTEX_POINT('',#918);
#920=EDGE_CURVE('E365',#919,#904,#917,.T.);
#921=ORIENTED_EDGE('',*,*,#920,.F.);
#922=CARTESIAN_POINT('',(10.9692481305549,33.2967396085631,28.2742814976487));
#923=CARTESIAN_POINT('',(11.3260085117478,32.2885806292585,27.9980977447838));
#924=CARTESIAN_POINT('',(11.696934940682,31.2806852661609,27.7390796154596));
#925=CARTESIAN_POINT('',(12.4670928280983,29.2670856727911,27.2565109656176));
#926=CARTESIAN_POINT('',(12.8663276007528,28.2613817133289,27.0329646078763));
#927=CARTESIAN_POINT('',(13.6933226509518,26.2532617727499,26.6223767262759));
#928=CARTESIAN_POINT('',(14.1211055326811,25.2508490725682,26.4353646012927));
#929=CARTESIAN_POINT('',(15.0046280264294,23.2520217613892,26.09935607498));
#930=CARTESIAN_POINT('',(15.4603665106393,22.2556069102,25.9503581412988));
#931=CARTESIAN_POINT('',(16.3866518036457,20.2975701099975,25.6951826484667));
#932=CARTESIAN_POINT('',(16.856462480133,19.3357371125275,25.5879539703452));
#933=CARTESIAN_POINT('',(17.8215710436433,17.421366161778,25.4118312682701));
#934=CARTESIAN_POINT('',(18.3168691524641,16.4688282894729,25.3429375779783));
#935=CARTESIAN_POINT('',(19.3319133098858,14.5754408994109,25.244377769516));
#936=CARTESIAN_POINT('',(19.8516466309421,13.6345856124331,25.2146914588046));
#937=CARTESIAN_POINT('',(20.9148310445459,11.7659834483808,25.1948994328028));
#938=CARTESIAN_POINT('',(21.4582812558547,10.8382360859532,25.2047922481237));
#939=CARTESIAN_POINT('',(22.4664782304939,9.16574803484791,25.2585998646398));
#940=CARTESIAN_POINT('',(22.9274734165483,8.41852749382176,25.2959715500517));
#941=CARTESIAN_POINT('',(23.8639232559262,6.9349635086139,25.3967050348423));
#942=CARTESIAN_POINT('',(24.3393789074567,6.19862082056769,25.4600686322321));
#943=CARTESIAN_POINT('',(25.7865743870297,4.00700419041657,25.6884453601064));
#944=CARTESIAN_POINT('',(26.7791523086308,2.56912581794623,25.8917449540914));
#945=CARTESIAN_POINT('',(28.3163403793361,0.436321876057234,26.2721992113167));
#946=CARTESIAN_POINT('',(28.8429125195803,-0.278400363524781,26.4136088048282));
#947=CARTESIAN_POINT('',(29.9082095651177,-1.69342791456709,26.7210827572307));
#948=CARTESIAN_POINT('',(30.4469346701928,-2.39373298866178,26.8871475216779));
#949=CARTESIAN_POINT('',(31.5354339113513,-3.77894448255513,27.2431748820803));
#950=CARTESIAN_POINT('',(32.0852027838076,-4.46385792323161,27.4331263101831));
#951=CARTESIAN_POINT('',(33.1951948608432,-5.81810405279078,27.8363627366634));
#952=CARTESIAN_POINT('',(33.7554174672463,-6.48743762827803,28.0496464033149));
#953=CARTESIAN_POINT('',(34.3204794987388,-7.14876096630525,28.2742946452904));
#954=B_SPLINE_CURVE_WITH_KNOTS('',3,(#922,#923,#924,#925,#926,#927,#928,#929,#930,#931,#932,
#933,#934,#935,#936,#937,#938,#939,#940,#941,#942,#943,#944,#945,#946,#947,#948,#949,#950,#951,
#952,#953),.UNSPECIFIED.,.F.,.F.,(4,2,2,2,2,2,2,2,2,2,2,2,2,2,2,4),(0.,3.31336634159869,
6.62712123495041,9.94353180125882,13.2598086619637,16.4862036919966,19.7126268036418,
22.9373875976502,26.162028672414,28.7977776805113,31.4337090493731,36.705516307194,
39.4019531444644,42.0984343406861,44.7936594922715,47.4887308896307),.UNSPECIFIED.);
#955=CARTESIAN_POINT('',(34.3203086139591,-7.14856096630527,28.2742267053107));
#956=VERTEX_POINT('',#955);
#957=EDGE_CURVE('E379',#919,#956,#954,.T.);
#958=ORIENTED_EDGE('',*,*,#957,.T.);
#959=CARTESIAN_POINT('',(35.9808712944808,-9.87751062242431,29.0336519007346));
#960=CARTESIAN_POINT('',(35.8792919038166,-9.62766704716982,28.9766995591));
#961=CARTESIAN_POINT('',(35.7677274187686,-9.38234121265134,28.9178353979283));
#962=CARTESIAN_POINT('',(35.5263312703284,-8.90361917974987,28.7970669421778));
#963=CARTESIAN_POINT('',(35.3966166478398,-8.67015867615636,28.7351836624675));
#964=CARTESIAN_POINT('',(35.1193480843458,-8.21494755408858,28.6084485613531));
#965=CARTESIAN_POINT('',(34.9717945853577,-7.99319664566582,28.5435968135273));
#966=CARTESIAN_POINT('',(34.6589304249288,-7.56130200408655,28.4109225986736));
#967=CARTESIAN_POINT('',(34.4935151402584,-7.35123894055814,28.3430841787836));
#968=CARTESIAN_POINT('',(34.3201377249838,-7.14836096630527,28.274158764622));
#969=B_SPLINE_CURVE_WITH_KNOTS('',3,(#959,#960,#961,#962,#963,#964,#965,#966,#967,#968),
.UNSPECIFIED.,.F.,.F.,(4,2,2,2,4),(0.,0.826702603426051,1.64830086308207,2.46987876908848,
3.29656081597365),.UNSPECIFIED.);
#970=EDGE_CURVE('E381',#424,#956,#969,.T.);
#971=ORIENTED_EDGE('',*,*,#970,.F.);
#972=ORIENTED_EDGE('',*,*,#478,.F.);
#973=CARTESIAN_POINT('',(22.9381321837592,-26.0623346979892,28.1643895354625));
#974=CARTESIAN_POINT('',(23.0065365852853,-26.078035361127,28.1828204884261));
#975=CARTESIAN_POINT('',(23.0751178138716,-26.0930191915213,28.2011824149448));
#976=CARTESIAN_POINT('',(23.2126756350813,-26.1215583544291,28.2377790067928));
#977=CARTESIAN_POINT('',(23.2816525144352,-26.1351124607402,28.2560135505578));
#978=CARTESIAN_POINT('',(23.611997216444,-26.1964110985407,28.3427868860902));
#979=CARTESIAN_POINT('',(23.875493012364,-26.2345314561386,28.4103444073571));
#980=CARTESIAN_POINT('',(24.4054258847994,-26.2896727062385,28.5429156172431));
#981=CARTESIAN_POINT('',(24.671864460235,-26.3066822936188,28.6079279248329));
#982=CARTESIAN_POINT('',(25.206427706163,-26.3193196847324,28.7350808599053));
#983=CARTESIAN_POINT('',(25.4745544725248,-26.3149111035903,28.7972164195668));
#984=CARTESIAN_POINT('',(26.0103526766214,-26.2844740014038,28.918085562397));
#985=CARTESIAN_POINT('',(26.2780241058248,-26.2584450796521,28.9768190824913));
#986=CARTESIAN_POINT('',(26.8172313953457,-26.1839073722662,29.0917710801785));
#987=CARTESIAN_POINT('',(27.0887175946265,-26.1349031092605,29.1479025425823));
#988=CARTESIAN_POINT('',(27.627556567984,-26.0143765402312,29.2557761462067));
#989=CARTESIAN_POINT('',(27.8949090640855,-25.9428527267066,29.3075179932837));
#990=CARTESIAN_POINT('',(28.423360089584,-25.777638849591,29.4061724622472));
#991=CARTESIAN_POINT('',(28.6844632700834,-25.6839658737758,29.4530887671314));
#992=CARTESIAN_POINT('',(29.1987127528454,-25.4748867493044,29.5417610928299));
#993=CARTESIAN_POINT('',(29.451859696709,-25.3594823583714,29.5835175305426));
#994=CARTESIAN_POINT('',(29.9258185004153,-25.1190005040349,29.6579934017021));
#995=CARTESIAN_POINT('',(30.1474824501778,-24.9957456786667,29.6911887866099));
#996=CARTESIAN_POINT('',(30.5812682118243,-24.7324235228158,29.7527955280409));
#997=CARTESIAN_POINT('',(30.793390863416,-24.5923576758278,29.7812073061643));
#998=CARTESIAN_POINT('',(31.2070373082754,-24.2959380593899,29.8330787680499));
#999=CARTESIAN_POINT('',(31.4085456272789,-24.1395614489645,29.8565313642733));
#1000=CARTESIAN_POINT('',(31.7993841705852,-23.8115585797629,29.8982717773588));
#1001=CARTESIAN_POINT('',(31.9887118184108,-23.6399291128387,29.9165585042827));
#1002=CARTESIAN_POINT('',(32.1712787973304,-23.4611433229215,29.9321764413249));
#1003=B_SPLINE_CURVE_WITH_KNOTS('',3,(#973,#974,#975,#976,#977,#978,#979,#980,#981,#982,#983,
#984,#985,#986,#987,#988,#989,#990,#991,#992,#993,#994,#995,#996,#997,#998,#999,#1000,#1001,
#1002),.UNSPECIFIED.,.F.,.F.,(4,2,2,2,2,2,2,2,2,2,2,2,2,2,4),(0.,0.21767295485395,
0.435531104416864,1.25862190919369,2.08215330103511,2.90708418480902,3.73203035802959,
4.57564846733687,5.41932306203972,6.26234888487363,7.10530654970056,7.87192045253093,
8.63846675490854,9.40610129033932,10.1738976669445),.UNSPECIFIED.);
#1004=CARTESIAN_POINT('',(23.3509897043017,-26.1479786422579,28.2742267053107));
#1005=VERTEX_POINT('',#1004);
#1006=EDGE_CURVE('E410',#1005,#475,#1003,.T.);
#1007=ORIENTED_EDGE('',*,*,#1006,.F.);
#1008=CARTESIAN_POINT('',(23.3511897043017,-26.1480157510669,28.2742792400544));
#1009=CARTESIAN_POINT('',(22.2997182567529,-25.9528998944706,27.9980955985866));
#1010=CARTESIAN_POINT('',(21.2413920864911,-25.770184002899,27.7390775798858));
#1011=CARTESIAN_POINT('',(19.1124848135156,-25.4303606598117,27.2565091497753));
#1012=CARTESIAN_POINT('',(18.0419022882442,-25.2732562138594,27.0329629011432));
#1013=CARTESIAN_POINT('',(15.8893219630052,-24.9853951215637,26.6223752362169));
#1014=CARTESIAN_POINT('',(14.8073157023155,-24.8546596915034,26.4353632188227));
#1015=CARTESIAN_POINT('',(12.6345193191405,-24.6203991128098,26.0993549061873));
#1016=CARTESIAN_POINT('',(11.5437295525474,-24.5168728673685,25.9503570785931));
#1017=CARTESIAN_POINT('',(9.38487735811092,-24.3400412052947,25.6951817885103));
#1018=CARTESIAN_POINT('',(8.31700022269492,-24.2659927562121,25.5879532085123));
#1019=CARTESIAN_POINT('',(6.17655209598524,-24.1446159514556,25.4118307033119));
#1020=CARTESIAN_POINT('',(5.10398106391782,-24.097287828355,25.3429371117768));
#1021=CARTESIAN_POINT('',(2.95673744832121,-24.0296482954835,25.2443775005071));
#1022=CARTESIAN_POINT('',(1.88206623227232,-24.0093229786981,25.2146912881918));
#1023=CARTESIAN_POINT('',(-0.267782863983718,-23.9957667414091,25.1948994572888));
#1024=CARTESIAN_POINT('',(-1.34296072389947,-24.0025348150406,25.2047923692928));
#1025=CARTESIAN_POINT('',(-3.2954735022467,-24.0394150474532,25.2586000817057));
#1026=CARTESIAN_POINT('',(-4.17308025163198,-24.0650382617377,25.2959716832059));
#1027=CARTESIAN_POINT('',(-5.926103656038,-24.1342453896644,25.396704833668));
#1028=CARTESIAN_POINT('',(-6.80152015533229,-24.1778305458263,25.4600681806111));
#1029=CARTESIAN_POINT('',(-9.42310520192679,-24.3353295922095,25.6884439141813));
#1030=CARTESIAN_POINT('',(-11.1646278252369,-24.4759874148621,25.8917425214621));
#1031=CARTESIAN_POINT('',(-13.7802759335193,-24.7408279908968,26.272194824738));
#1032=CARTESIAN_POINT('',(-14.6625267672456,-24.8394911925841,26.4136036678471));
#1033=CARTESIAN_POINT('',(-16.4206194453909,-25.0545505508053,26.7210759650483));
#1034=CARTESIAN_POINT('',(-17.2964611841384,-25.170946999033,26.887139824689));
#1035=CARTESIAN_POINT('',(-19.0403336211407,-25.4210078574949,27.2431652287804));
#1036=CARTESIAN_POINT('',(-19.9083677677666,-25.5546641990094,27.4331156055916));
#1037=CARTESIAN_POINT('',(-21.6361699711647,-25.838820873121,27.8363497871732));
#1038=CARTESIAN_POINT('',(-22.4959384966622,-25.9893202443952,28.049632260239));
#1039=CARTESIAN_POINT('',(-23.3511897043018,-26.1480157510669,28.2742792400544));
#1040=B_SPLINE_CURVE_WITH_KNOTS('',3,(#1008,#1009,#1010,#1011,#1012,#1013,#1014,#1015,#1016,
#1017,#1018,#1019,#1020,#1021,#1022,#1023,#1024,#1025,#1026,#1027,#1028,#1029,#1030,#1031,#1032,
#1033,#1034,#1035,#1036,#1037,#1038,#1039),.UNSPECIFIED.,.F.,.F.,(4,2,2,2,2,2,2,2,2,2,2,2,2,2,2,
4),(0.,3.31336612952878,6.62712081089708,9.94353116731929,13.2598078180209,16.486202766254,
19.7126257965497,22.9373865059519,26.1620274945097,28.7977680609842,31.4336909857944,
36.7054813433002,39.4019092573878,42.0983815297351,44.7935977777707,47.4886602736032),.UNSPECIFIED.);
#1041=CARTESIAN_POINT('',(-23.3509897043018,-26.1479786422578,28.2742267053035));
#1042=VERTEX_POINT('',#1041);
#1043=EDGE_CURVE('E455',#1005,#1042,#1040,.T.);
#1044=ORIENTED_EDGE('',*,*,#1043,.T.);
#1045=CARTESIAN_POINT('',(-32.1712783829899,-23.461143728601,29.9321764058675));
#1046=CARTESIAN_POINT('',(-31.9756513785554,-23.6527280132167,29.9154425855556));
#1047=CARTESIAN_POINT('',(-31.7722564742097,-23.836087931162,29.8956420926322));
#1048=CARTESIAN_POINT('',(-31.3515682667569,-24.1852279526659,29.8501200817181));
#1049=CARTESIAN_POINT('',(-31.1342770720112,-24.3510107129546,29.8243994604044));
#1050=CARTESIAN_POINT('',(-30.6879565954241,-24.6635157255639,29.7673188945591));
#1051=CARTESIAN_POINT('',(-30.4589594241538,-24.8102865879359,29.7359738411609));
#1052=CARTESIAN_POINT('',(-29.9903909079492,-25.0843936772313,29.6678603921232));
#1053=CARTESIAN_POINT('',(-29.7508197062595,-25.2117301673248,29.631092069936));
#1054=CARTESIAN_POINT('',(-29.2722935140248,-25.4417002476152,29.553952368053));
#1055=CARTESIAN_POINT('',(-29.033674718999,-25.5451001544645,29.513775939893));
#1056=CARTESIAN_POINT('',(-28.5498011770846,-25.732794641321,29.4289705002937));
#1057=CARTESIAN_POINT('',(-28.3045462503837,-25.8170887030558,29.384341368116));
#1058=CARTESIAN_POINT('',(-27.8087760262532,-25.9662709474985,29.2909052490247));
#1059=CARTESIAN_POINT('',(-27.5582568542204,-26.0311442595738,29.2420950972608));
#1060=CARTESIAN_POINT('',(-27.0536954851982,-26.1411776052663,29.1406543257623));
#1061=CARTESIAN_POINT('',(-26.7996532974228,-26.18633769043,29.0880237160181));
#1062=CARTESIAN_POINT('',(-26.2780559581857,-26.2584402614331,28.9768258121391));
#1063=CARTESIAN_POINT('',(-26.0104084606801,-26.2844684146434,28.9180977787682));
#1064=CARTESIAN_POINT('',(-25.4746554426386,-26.3149077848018,28.7972395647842));
#1065=CARTESIAN_POINT('',(-25.2065499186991,-26.3193188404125,28.7351093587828));
#1066=CARTESIAN_POINT('',(-24.6719823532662,-26.3066888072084,28.607956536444));
#1067=CARTESIAN_POINT('',(-24.405518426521,-26.289680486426,28.5429384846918));
#1068=CARTESIAN_POINT('',(-23.8755377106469,-26.2345379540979,28.4103558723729));
#1069=CARTESIAN_POINT('',(-23.6120193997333,-26.196415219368,28.3427927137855));
#1070=CARTESIAN_POINT('',(-23.2816512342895,-26.1351122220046,28.2560132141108));
#1071=CARTESIAN_POINT('',(-23.212673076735,-26.1215578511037,28.2377783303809));
#1072=CARTESIAN_POINT('',(-23.075115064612,-26.093018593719,28.2011816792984));
#1073=CARTESIAN_POINT('',(-23.0065349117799,-26.0780349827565,28.1828200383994));
#1074=CARTESIAN_POINT('',(-22.9381315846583,-26.0623345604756,28.1643893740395));
#1075=B_SPLINE_CURVE_WITH_KNOTS('',3,(#1045,#1046,#1047,#1048,#1049,#1050,#1051,#1052,#1053,
#1054,#1055,#1056,#1057,#1058,#1059,#1060,#1061,#1062,#1063,#1064,#1065,#1066,#1067,#1068,#1069,
#1070,#1071,#1072,#1073,#1074),.UNSPECIFIED.,.F.,.F.,(4,2,2,2,2,2,2,2,2,2,2,2,2,2,4),(0.,
0.822704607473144,1.64528468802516,2.46571822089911,3.28614064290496,4.07475604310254,
4.86339283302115,5.65263195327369,6.44186900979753,7.2667312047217,8.09159955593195,
8.91520752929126,9.73836826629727,9.95623045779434,10.173900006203),.UNSPECIFIED.);
#1076=EDGE_CURVE('E239',#332,#1042,#1075,.T.);
#1077=ORIENTED_EDGE('',*,*,#1076,.F.);
#1078=ORIENTED_EDGE('',*,*,#333,.F.);
#1079=EDGE_LOOP('',(#850,#887,#902,#906,#921,#958,#971,#972,#1007,#1044,#1077,#1078));
#1080=FACE_BOUND('',#1079,.T.);
#1081=ADVANCED_FACE('F251',(#835,#1080),#832,.F.);
#1082=CARTESIAN_POINT('',(-2.05632703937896,39.9471090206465,32.8123490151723));
#1083=CARTESIAN_POINT('',(-2.06306964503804,39.9467619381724,32.8086510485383));
#1084=CARTESIAN_POINT('',(-2.06981196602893,39.9464080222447,32.8049530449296));
#1085=CARTESIAN_POINT('',(-2.37288776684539,39.9301911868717,32.6387146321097));
#1086=CARTESIAN_POINT('',(-2.66865054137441,39.9011342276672,32.4761219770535));
#1087=CARTESIAN_POINT('',(-3.25727915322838,39.8166559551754,32.1524635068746));
#1088=CARTESIAN_POINT('',(-3.5501440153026,39.7612260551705,31.9913982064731));
#1089=CARTESIAN_POINT('',(-4.13227456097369,39.6237396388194,31.6718948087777));
#1090=CARTESIAN_POINT('',(-4.42152644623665,39.541601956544,31.5134662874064));
#1091=CARTESIAN_POINT('',(-4.99373305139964,39.3506551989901,31.2015436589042));
#1092=CARTESIAN_POINT('',(-5.27668967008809,39.2418542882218,31.0480480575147));
#1093=CARTESIAN_POINT('',(-5.79872937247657,39.0131101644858,30.7672178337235));
#1094=CARTESIAN_POINT('',(-6.03878127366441,38.8963907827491,30.6390545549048));
#1095=CARTESIAN_POINT('',(-6.51149488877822,38.6424140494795,30.3894768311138));
#1096=CARTESIAN_POINT('',(-6.74415584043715,38.5051545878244,30.2680630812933));
#1097=CARTESIAN_POINT('',(-7.19972791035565,38.2105552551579,30.0342656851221));
#1098=CARTESIAN_POINT('',(-7.42267250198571,38.0532930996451,29.9218496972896));
#1099=CARTESIAN_POINT('',(-7.8579898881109,37.7183449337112,29.7077785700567));
#1100=CARTESIAN_POINT('',(-8.07036775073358,37.540668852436,29.6061182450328));
#1101=CARTESIAN_POINT('',(-8.4837854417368,37.1640465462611,29.4157240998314));
#1102=CARTESIAN_POINT('',(-8.68476979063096,36.9650079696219,29.3270506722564));
#1103=CARTESIAN_POINT('',(-8.97542067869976,36.6512439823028,29.2066636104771));
#1104=CARTESIAN_POINT('',(-9.07060234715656,36.5439906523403,29.1686022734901));
#1105=CARTESIAN_POINT('',(-9.2570410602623,36.3245024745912,29.0972287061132));
#1106=CARTESIAN_POINT('',(-9.34829595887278,36.2122649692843,29.0639190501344));
#1107=CARTESIAN_POINT('',(-9.43742318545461,36.0976085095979,29.0332519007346));
#1108=B_SPLINE_CURVE_WITH_KNOTS('',3,(#1082,#1083,#1084,#1085,#1086,#1087,#1088,#1089,#1090,
#1091,#1092,#1093,#1094,#1095,#1096,#1097,#1098,#1099,#1100,#1101,#1102,#1103,#1104,#1105,#1106,
#1107),.UNSPECIFIED.,.F.,.F.,(4,2,2,2,2,2,2,2,2,2,2,2,4),(0.,0.0230940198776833,
1.03815072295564,2.05353814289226,3.07204066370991,4.09023169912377,4.97770245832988,
5.8652644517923,6.74947775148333,7.63326278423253,8.52103536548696,8.96593722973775,
9.41107922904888),.UNSPECIFIED.);
#1109=CARTESIAN_POINT('',(-2.05632636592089,39.9471090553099,32.8123490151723));
#1110=VERTEX_POINT('',#1109);
#1111=EDGE_CURVE('E290',#1110,#900,#1108,.T.);
#1112=ORIENTED_EDGE('',*,*,#1111,.F.);
#1113=CARTESIAN_POINT('',(2.05632703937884,39.9471090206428,32.8123490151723));
#1114=VERTEX_POINT('',#1113);
#1115=EDGE_CURVE('E176',#1114,#1110,#388,.T.);
#1116=ORIENTED_EDGE('',*,*,#1115,.F.);
#1117=CARTESIAN_POINT('',(9.43742318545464,36.0976085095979,29.0332519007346));
#1118=CARTESIAN_POINT('',(9.36280541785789,36.1935994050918,29.0589236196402));
#1119=CARTESIAN_POINT('',(9.28669295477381,36.287899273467,29.0864524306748));
#1120=CARTESIAN_POINT('',(9.13165878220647,36.4730407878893,29.1449110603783));
#1121=CARTESIAN_POINT('',(9.05273765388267,36.5638831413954,29.1758401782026));
#1122=CARTESIAN_POINT('',(8.81222629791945,36.8308993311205,29.2731775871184));
#1123=CARTESIAN_POINT('',(8.64666218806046,37.001851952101,29.3442151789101));
#1124=CARTESIAN_POINT('',(8.3071146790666,37.3286310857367,29.4961478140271));
#1125=CARTESIAN_POINT('',(8.13317240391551,37.4845220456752,29.576997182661));
#1126=CARTESIAN_POINT('',(7.77724937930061,37.7820037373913,29.7471258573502));
#1127=CARTESIAN_POINT('',(7.59526482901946,37.9235876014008,29.8364091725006));
#1128=CARTESIAN_POINT('',(7.16802797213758,38.2331590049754,30.0501050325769));
#1129=CARTESIAN_POINT('',(6.92033554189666,38.3961201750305,30.1769557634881));
#1130=CARTESIAN_POINT('',(6.4152617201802,38.6976272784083,30.4398055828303));
#1131=CARTESIAN_POINT('',(6.15787840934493,38.8361683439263,30.5758064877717));
#1132=CARTESIAN_POINT('',(5.37281537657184,39.2158508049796,30.9948167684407));
#1133=CARTESIAN_POINT('',(4.83273542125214,39.4206856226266,31.2885714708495));
#1134=CARTESIAN_POINT('',(3.92151508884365,39.6804720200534,31.7873414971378));
#1135=CARTESIAN_POINT('',(3.5555266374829,39.7627132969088,31.9884816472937));
#1136=CARTESIAN_POINT('',(2.81880695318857,39.8855181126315,32.3935479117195));
#1137=CARTESIAN_POINT('',(2.44808705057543,39.9261672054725,32.5974674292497));
#1138=CARTESIAN_POINT('',(2.0698119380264,39.9464080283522,32.8049530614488));
#1139=CARTESIAN_POINT('',(2.06306961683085,39.9467619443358,32.8086510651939));
#1140=CARTESIAN_POINT('',(2.05632703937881,39.9471090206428,32.8123490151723));
#1141=B_SPLINE_CURVE_WITH_KNOTS('',3,(#1117,#1118,#1119,#1120,#1121,#1122,#1123,#1124,#1125,
#1126,#1127,#1128,#1129,#1130,#1131,#1132,#1133,#1134,#1135,#1136,#1137,#1138,#1139,#1140),
.UNSPECIFIED.,.F.,.F.,(4,2,2,2,2,2,2,2,2,2,2,4),(0.,0.372708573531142,0.745340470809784,
1.48948087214,2.23028131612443,2.97143569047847,3.93750896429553,4.90377459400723,
6.83832849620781,8.11359476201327,9.38623253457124,9.40932655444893),.UNSPECIFIED.);
#1142=EDGE_CURVE('E281',#904,#1114,#1141,.T.);
#1143=ORIENTED_EDGE('',*,*,#1142,.F.);
#1144=ORIENTED_EDGE('',*,*,#905,.T.);
#1145=EDGE_LOOP('',(#1112,#1116,#1143,#1144));
#1146=FACE_BOUND('',#1145,.T.);
#1147=ADVANCED_FACE('F246',(#1146),#294,.T.);
#1148=CARTESIAN_POINT('',(2.05632703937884,39.9471090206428,42.7952303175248));
#1149=VERTEX_POINT('',#1148);
#1150=CARTESIAN_POINT('',(-2.05632636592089,39.9471090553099,42.7952303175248));
#1151=VERTEX_POINT('',#1150);
#1152=EDGE_CURVE('E166',#1149,#1151,#500,.T.);
#1153=ORIENTED_EDGE('',*,*,#1152,.F.);
#1154=DIRECTION('',(0.,0.,-1.));
#1155=VECTOR('',#1154,1.);
#1156=CARTESIAN_POINT('',(2.05632703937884,39.9471090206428,53.5));
#1157=LINE('',#1156,#1155);
#1158=EDGE_CURVE('E492',#1149,#1114,#1157,.T.);
#1159=ORIENTED_EDGE('',*,*,#1158,.T.);
#1160=ORIENTED_EDGE('',*,*,#1115,.T.);
#1161=DIRECTION('',(0.,0.,-1.));
#1162=VECTOR('',#1161,1.);
#1163=CARTESIAN_POINT('',(-2.05632636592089,39.9471090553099,53.5));
#1164=LINE('',#1163,#1162);
#1165=EDGE_CURVE('E490',#1151,#1110,#1164,.T.);
#1166=ORIENTED_EDGE('',*,*,#1165,.F.);
#1167=EDGE_LOOP('',(#1153,#1159,#1160,#1166));
#1168=FACE_BOUND('',#1167,.T.);
#1169=ADVANCED_FACE('F250',(#1168),#487,.T.);
#1170=CARTESIAN_POINT('',(-9.3045124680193,36.2648704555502,46.5272395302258));
#1171=CARTESIAN_POINT('',(-9.22647166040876,36.3609557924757,46.4988173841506));
#1172=CARTESIAN_POINT('',(-9.14692864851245,36.4552447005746,46.468560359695));
#1173=CARTESIAN_POINT('',(-8.98502380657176,36.6401632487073,46.4046918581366));
#1174=CARTESIAN_POINT('',(-8.90266254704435,36.7307936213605,46.3710810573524));
#1175=CARTESIAN_POINT('',(-8.65182764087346,36.9968932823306,46.2657756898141));
#1176=CARTESIAN_POINT('',(-8.47937248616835,37.1668537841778,46.1895227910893));
#1177=CARTESIAN_POINT('',(-8.12599426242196,37.4910383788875,46.0273374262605));
#1178=CARTESIAN_POINT('',(-7.94510699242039,37.6453214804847,45.941444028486));
#1179=CARTESIAN_POINT('',(-7.57533050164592,37.9389056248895,45.7614171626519));
#1180=CARTESIAN_POINT('',(-7.38643760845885,38.0781996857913,45.6672798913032));
#1181=CARTESIAN_POINT('',(-6.94496034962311,38.3806563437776,45.443435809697));
#1182=CARTESIAN_POINT('',(-6.69003816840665,38.5387225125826,45.3114336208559));
#1183=CARTESIAN_POINT('',(-6.17070385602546,38.8297175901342,45.038684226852));
#1184=CARTESIAN_POINT('',(-5.90628975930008,38.9626412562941,44.8979352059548));
#1185=CARTESIAN_POINT('',(-5.3694913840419,39.2036452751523,44.6096660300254));
#1186=CARTESIAN_POINT('',(-5.09709790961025,39.3116955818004,44.4621379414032));
#1187=CARTESIAN_POINT('',(-4.546275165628,39.5029103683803,44.162277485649));
#1188=CARTESIAN_POINT('',(-4.26784522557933,39.5860720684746,44.0099445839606));
#1189=CARTESIAN_POINT('',(-3.67274427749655,39.7361253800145,43.6835729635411));
#1190=CARTESIAN_POINT('',(-3.35550064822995,39.7998583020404,43.5091267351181));
#1191=CARTESIAN_POINT('',(-2.71790494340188,39.8962037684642,43.1585370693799));
#1192=CARTESIAN_POINT('',(-2.39755934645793,39.92887107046,42.9823971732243));
#1193=CARTESIAN_POINT('',(-2.06981196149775,39.9464080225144,42.8026262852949));
#1194=CARTESIAN_POINT('',(-2.06306964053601,39.9467619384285,42.7989282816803));
#1195=CARTESIAN_POINT('',(-2.05632703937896,39.9471090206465,42.7952303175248));
#1196=B_SPLINE_CURVE_WITH_KNOTS('',3,(#1170,#1171,#1172,#1173,#1174,#1175,#1176,#1177,#1178,
#1179,#1180,#1181,#1182,#1183,#1184,#1185,#1186,#1187,#1188,#1189,#1190,#1191,#1192,#1193,#1194,
#1195),.UNSPECIFIED.,.F.,.F.,(4,2,2,2,2,2,2,2,2,2,2,2,4),(0.,0.38093944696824,0.761802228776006,
1.52240816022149,2.28003601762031,3.03801526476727,4.01980078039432,5.00179078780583,
5.98496084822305,6.96824067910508,8.06975144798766,9.16931702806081,9.19241104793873),.UNSPECIFIED.);
#1197=EDGE_CURVE('E299',#47,#1151,#1196,.T.);
#1198=ORIENTED_EDGE('',*,*,#1197,.F.);
#1199=ORIENTED_EDGE('',*,*,#48,.F.);
#1200=CARTESIAN_POINT('',(2.05632703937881,39.9471090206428,42.7952303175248));
#1201=CARTESIAN_POINT('',(2.06306964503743,39.9467619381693,42.7989282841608));
#1202=CARTESIAN_POINT('',(2.06981196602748,39.9464080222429,42.802626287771));
#1203=CARTESIAN_POINT('',(2.37288962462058,39.9301910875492,42.9688657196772));
#1204=CARTESIAN_POINT('',(2.6686542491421,39.9011338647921,43.1314593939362));
#1205=CARTESIAN_POINT('',(3.25728651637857,39.8166547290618,43.4551198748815));
#1206=CARTESIAN_POINT('',(3.55015318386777,39.7612242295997,43.6161861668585));
#1207=CARTESIAN_POINT('',(4.13228427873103,39.623737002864,43.9356898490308));
#1208=CARTESIAN_POINT('',(4.42153495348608,39.5415993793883,44.0941176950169));
#1209=CARTESIAN_POINT('',(4.99373791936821,39.3506533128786,44.4060383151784));
#1210=CARTESIAN_POINT('',(5.27669213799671,39.2418531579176,44.559532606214));
#1211=CARTESIAN_POINT('',(5.79872322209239,39.0131129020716,44.8403581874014));
#1212=CARTESIAN_POINT('',(6.038769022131,38.8963968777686,44.9685182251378));
#1213=CARTESIAN_POINT('',(6.51147583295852,38.6424247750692,45.2180925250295));
#1214=CARTESIAN_POINT('',(6.74413595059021,38.5051662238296,45.3395059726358));
#1215=CARTESIAN_POINT('',(7.1997164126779,38.210563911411,45.5733078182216));
#1216=CARTESIAN_POINT('',(7.4226697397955,38.0532966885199,45.6857280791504));
#1217=CARTESIAN_POINT('',(7.85800041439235,37.7183353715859,45.8998061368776));
#1218=CARTESIAN_POINT('',(8.07038351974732,37.5406525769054,46.001469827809));
#1219=CARTESIAN_POINT('',(8.45837411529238,37.1871978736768,46.1801510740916));
#1220=CARTESIAN_POINT('',(8.63535539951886,37.0136998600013,46.258661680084));
#1221=CARTESIAN_POINT('',(8.89262915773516,36.7417378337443,46.366957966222));
#1222=CARTESIAN_POINT('',(8.97708126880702,36.649057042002,46.4015009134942));
#1223=CARTESIAN_POINT('',(9.14305281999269,36.4598369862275,46.46708507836));
#1224=CARTESIAN_POINT('',(9.22457101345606,36.3632961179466,46.4981248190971));
#1225=CARTESIAN_POINT('',(9.30451246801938,36.2648704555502,46.5272395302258));
#1226=B_SPLINE_CURVE_WITH_KNOTS('',3,(#1200,#1201,#1202,#1203,#1204,#1205,#1206,#1207,#1208,
#1209,#1210,#1211,#1212,#1213,#1214,#1215,#1216,#1217,#1218,#1219,#1220,#1221,#1222,#1223,#1224,
#1225),.UNSPECIFIED.,.F.,.F.,(4,2,2,2,2,2,2,2,2,2,2,2,4),(0.,0.0230940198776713,
1.03815708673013,2.05355085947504,3.0720493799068,4.09023169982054,4.97768026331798,
5.86523574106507,6.74949279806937,7.63326278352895,8.41219026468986,8.80224241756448,
9.19245839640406),.UNSPECIFIED.);
#1227=EDGE_CURVE('E372',#1149,#36,#1226,.T.);
#1228=ORIENTED_EDGE('',*,*,#1227,.F.);
#1229=ORIENTED_EDGE('',*,*,#1152,.T.);
#1230=EDGE_LOOP('',(#1198,#1199,#1228,#1229));
#1231=FACE_BOUND('',#1230,.T.);
#1232=ADVANCED_FACE('F219',(#1231),#541,.T.);
#1233=CARTESIAN_POINT('',(-25.1752857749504,-16.3157894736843,53.5));
#1234=DIRECTION('',(0.,0.,-1.));
#1235=DIRECTION('',(-1.,0.,0.));
#1236=AXIS2_PLACEMENT_3D('',#1233,#1234,#1235);
#1237=CYLINDRICAL_SURFACE('',#1236,10.);
#1238=ORIENTED_EDGE('',*,*,#1076,.T.);
#1239=DIRECTION('',(0.,0.,-1.));
#1240=VECTOR('',#1239,1.);
#1241=CARTESIAN_POINT('',(-23.3509897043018,-26.1479786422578,53.5));
#1242=LINE('',#1241,#1240);
#1243=EDGE_CURVE('E160',#151,#1042,#1242,.T.);
#1244=ORIENTED_EDGE('',*,*,#1243,.F.);
#1245=ORIENTED_EDGE('',*,*,#152,.T.);
#1246=ORIENTED_EDGE('',*,*,#635,.T.);
#1247=ORIENTED_EDGE('',*,*,#532,.T.);
#1248=ORIENTED_EDGE('',*,*,#382,.T.);
#1249=EDGE_LOOP('',(#1238,#1244,#1245,#1246,#1247,#1248));
#1250=FACE_BOUND('',#1249,.T.);
#1251=ADVANCED_FACE('F140',(#1250),#1237,.T.);
#1252=CARTESIAN_POINT('',(-1.3010426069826E-13,-152.,53.5));
#1253=DIRECTION('',(0.,0.,-1.));
#1254=DIRECTION('',(-1.,0.,0.));
#1255=AXIS2_PLACEMENT_3D('',#1252,#1253,#1254);
#1256=CYLINDRICAL_SURFACE('',#1255,128.);
#1257=DIRECTION('',(0.,0.,-1.));
#1258=VECTOR('',#1257,1.);
#1259=CARTESIAN_POINT('',(23.3509897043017,-26.1479786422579,53.5));
#1260=LINE('',#1259,#1258);
#1261=EDGE_CURVE('E467',#186,#1005,#1260,.T.);
#1262=ORIENTED_EDGE('',*,*,#1261,.F.);
#1263=ORIENTED_EDGE('',*,*,#187,.F.);
#1264=ORIENTED_EDGE('',*,*,#1243,.T.);
#1265=ORIENTED_EDGE('',*,*,#1043,.F.);
#1266=EDGE_LOOP('',(#1262,#1263,#1264,#1265));
#1267=FACE_BOUND('',#1266,.T.);
#1268=ADVANCED_FACE('F218',(#1267),#1256,.F.);
#1269=CARTESIAN_POINT('',(25.1752857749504,-16.3157894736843,53.5));
#1270=DIRECTION('',(0.,0.,-1.));
#1271=DIRECTION('',(-1.,0.,0.));
#1272=AXIS2_PLACEMENT_3D('',#1269,#1270,#1271);
#1273=CYLINDRICAL_SURFACE('',#1272,10.);
#1274=ORIENTED_EDGE('',*,*,#1006,.T.);
#1275=ORIENTED_EDGE('',*,*,#476,.T.);
#1276=ORIENTED_EDGE('',*,*,#509,.F.);
#1277=ORIENTED_EDGE('',*,*,#714,.T.);
#1278=ORIENTED_EDGE('',*,*,#222,.T.);
#1279=ORIENTED_EDGE('',*,*,#1261,.T.);
#1280=EDGE_LOOP('',(#1274,#1275,#1276,#1277,#1278,#1279));
#1281=FACE_BOUND('',#1280,.T.);
#1282=ADVANCED_FACE('F419',(#1281),#1273,.T.);
#1283=CARTESIAN_POINT('',(26.7175310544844,-13.6445422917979,53.5));
#1284=DIRECTION('',(0.,0.,-1.));
#1285=DIRECTION('',(-1.,0.,0.));
#1286=AXIS2_PLACEMENT_3D('',#1283,#1284,#1285);
#1287=CYLINDRICAL_SURFACE('',#1286,10.);
#1288=ORIENTED_EDGE('',*,*,#970,.T.);
#1289=DIRECTION('',(0.,0.,-1.));
#1290=VECTOR('',#1289,1.);
#1291=CARTESIAN_POINT('',(34.3203086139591,-7.14856096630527,53.5));
#1292=LINE('',#1291,#1290);
#1293=EDGE_CURVE('E37',#240,#956,#1292,.T.);
#1294=ORIENTED_EDGE('',*,*,#1293,.F.);
#1295=ORIENTED_EDGE('',*,*,#241,.T.);
#1296=ORIENTED_EDGE('',*,*,#668,.T.);
#1297=ORIENTED_EDGE('',*,*,#494,.T.);
#1298=ORIENTED_EDGE('',*,*,#425,.T.);
#1299=EDGE_LOOP('',(#1288,#1294,#1295,#1296,#1297,#1298));
#1300=FACE_BOUND('',#1299,.T.);
#1301=ADVANCED_FACE('F415',(#1300),#1287,.T.);
#1302=CARTESIAN_POINT('',(131.635861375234,76.,53.5));
#1303=DIRECTION('',(0.,0.,-1.));
#1304=DIRECTION('',(-1.,0.,0.));
#1305=AXIS2_PLACEMENT_3D('',#1302,#1303,#1304);
#1306=CYLINDRICAL_SURFACE('',#1305,127.999999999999);
#1307=DIRECTION('',(0.,0.,-1.));
#1308=VECTOR('',#1307,1.);
#1309=CARTESIAN_POINT('',(10.9693189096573,33.2965396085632,53.5));
#1310=LINE('',#1309,#1308);
#1311=EDGE_CURVE('E494',#38,#919,#1310,.T.);
#1312=ORIENTED_EDGE('',*,*,#1311,.F.);
#1313=ORIENTED_EDGE('',*,*,#274,.F.);
#1314=ORIENTED_EDGE('',*,*,#1293,.T.);
#1315=ORIENTED_EDGE('',*,*,#957,.F.);
#1316=EDGE_LOOP('',(#1312,#1313,#1314,#1315));
#1317=FACE_BOUND('',#1316,.T.);
#1318=ADVANCED_FACE('F418',(#1317),#1306,.F.);
#1319=CARTESIAN_POINT('',(1.54224527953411,29.9603317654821,53.5));
#1320=DIRECTION('',(0.,0.,-1.));
#1321=DIRECTION('',(-1.,0.,0.));
#1322=AXIS2_PLACEMENT_3D('',#1319,#1320,#1321);
#1323=CYLINDRICAL_SURFACE('',#1322,10.);
#1324=ORIENTED_EDGE('',*,*,#920,.T.);
#1325=ORIENTED_EDGE('',*,*,#1142,.T.);
#1326=ORIENTED_EDGE('',*,*,#1158,.F.);
#1327=ORIENTED_EDGE('',*,*,#1227,.T.);
#1328=ORIENTED_EDGE('',*,*,#39,.T.);
#1329=ORIENTED_EDGE('',*,*,#1311,.T.);
#1330=EDGE_LOOP('',(#1324,#1325,#1326,#1327,#1328,#1329));
#1331=FACE_BOUND('',#1330,.T.);
#1332=ADVANCED_FACE('F317',(#1331),#1323,.T.);
#1333=CARTESIAN_POINT('',(-26.7175310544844,-13.6445422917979,53.5));
#1334=DIRECTION('',(0.,0.,-1.));
#1335=DIRECTION('',(-1.,0.,0.));
#1336=AXIS2_PLACEMENT_3D('',#1333,#1334,#1335);
#1337=CYLINDRICAL_SURFACE('',#1336,10.);
#1338=ORIENTED_EDGE('',*,*,#849,.T.);
#1339=ORIENTED_EDGE('',*,*,#324,.T.);
#1340=ORIENTED_EDGE('',*,*,#525,.F.);
#1341=ORIENTED_EDGE('',*,*,#587,.T.);
#1342=ORIENTED_EDGE('',*,*,#113,.T.);
#1343=DIRECTION('',(0.,0.,-1.));
#1344=VECTOR('',#1343,1.);
#1345=CARTESIAN_POINT('',(-34.3203086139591,-7.14856096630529,53.5));
#1346=LINE('',#1345,#1344);
#1347=EDGE_CURVE('E150',#97,#848,#1346,.T.);
#1348=ORIENTED_EDGE('',*,*,#1347,.T.);
#1349=EDGE_LOOP('',(#1338,#1339,#1340,#1341,#1342,#1348));
#1350=FACE_BOUND('',#1349,.T.);
#1351=ADVANCED_FACE('F222',(#1350),#1337,.T.);
#1352=CARTESIAN_POINT('',(-131.635861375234,76.,53.5));
#1353=DIRECTION('',(0.,0.,-1.));
#1354=DIRECTION('',(-1.,0.,0.));
#1355=AXIS2_PLACEMENT_3D('',#1352,#1353,#1354);
#1356=CYLINDRICAL_SURFACE('',#1355,128.);
#1357=ORIENTED_EDGE('',*,*,#1347,.F.);
#1358=ORIENTED_EDGE('',*,*,#98,.F.);
#1359=DIRECTION('',(0.,0.,-1.));
#1360=VECTOR('',#1359,1.);
#1361=CARTESIAN_POINT('',(-10.9693189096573,33.2965396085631,53.5));
#1362=LINE('',#1361,#1360);
#1363=EDGE_CURVE('E29',#62,#885,#1362,.T.);
#1364=ORIENTED_EDGE('',*,*,#1363,.T.);
#1365=ORIENTED_EDGE('',*,*,#886,.F.);
#1366=EDGE_LOOP('',(#1357,#1358,#1364,#1365));
#1367=FACE_BOUND('',#1366,.T.);
#1368=ADVANCED_FACE('F314',(#1367),#1356,.F.);
#1369=CARTESIAN_POINT('',(-1.54224527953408,29.9603317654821,53.5));
#1370=DIRECTION('',(0.,0.,-1.));
#1371=DIRECTION('',(-1.,0.,0.));
#1372=AXIS2_PLACEMENT_3D('',#1369,#1370,#1371);
#1373=CYLINDRICAL_SURFACE('',#1372,10.);
#1374=ORIENTED_EDGE('',*,*,#901,.T.);
#1375=ORIENTED_EDGE('',*,*,#1363,.F.);
#1376=ORIENTED_EDGE('',*,*,#63,.T.);
#1377=ORIENTED_EDGE('',*,*,#1197,.T.);
#1378=ORIENTED_EDGE('',*,*,#1165,.T.);
#1379=ORIENTED_EDGE('',*,*,#1111,.T.);
#1380=EDGE_LOOP('',(#1374,#1375,#1376,#1377,#1378,#1379));
#1381=FACE_BOUND('',#1380,.T.);
#1382=ADVANCED_FACE('F309',(#1381),#1373,.T.);
#1383=CARTESIAN_POINT('',(0.,0.,53.5));
#1384=DIRECTION('',(0.,0.,1.));
#1385=DIRECTION('',(1.,0.,0.));
#1386=AXIS2_PLACEMENT_3D('',#1383,#1384,#1385);
#1387=CYLINDRICAL_SURFACE('',#1386,15.);
#1388=CARTESIAN_POINT('',(0.,0.,53.5));
#1389=DIRECTION('',(0.,0.,1.));
#1390=DIRECTION('',(1.,0.,0.));
#1391=AXIS2_PLACEMENT_3D('',#1388,#1389,#1390);
#1392=CIRCLE('',#1391,15.);
#1393=CARTESIAN_POINT('',(15.,0.,53.5));
#1394=VERTEX_POINT('',#1393);
#1395=EDGE_CURVE('E478',#1394,#1394,#1392,.T.);
#1396=ORIENTED_EDGE('',*,*,#1395,.F.);
#1397=EDGE_LOOP('',(#1396));
#1398=FACE_BOUND('',#1397,.T.);
#1399=ORIENTED_EDGE('',*,*,#285,.F.);
#1400=EDGE_LOOP('',(#1399));
#1401=FACE_BOUND('',#1400,.T.);
#1402=ADVANCED_FACE('F313',(#1398,#1401),#1387,.T.);
#1403=CARTESIAN_POINT('',(0.,15.,53.5));
#1404=DIRECTION('',(0.,0.,-1.));
#1405=DIRECTION('',(-1.,0.,0.));
#1406=AXIS2_PLACEMENT_3D('',#1403,#1404,#1405);
#1407=PLANE('',#1406);
#1408=ORIENTED_EDGE('',*,*,#1395,.T.);
#1409=EDGE_LOOP('',(#1408));
#1410=FACE_BOUND('',#1409,.T.);
#1411=ADVANCED_FACE('F709',(#1410),#1407,.F.);
#1412=CARTESIAN_POINT('',(0.,0.,12.));
#1413=DIRECTION('',(0.,0.,-1.));
#1414=DIRECTION('',(-1.,0.,0.));
#1415=AXIS2_PLACEMENT_3D('',#1412,#1413,#1414);
#1416=CYLINDRICAL_SURFACE('',#1415,5.);
#1417=CARTESIAN_POINT('',(0.,0.,12.));
#1418=DIRECTION('',(0.,0.,-1.));
#1419=DIRECTION('',(-1.,0.,0.));
#1420=AXIS2_PLACEMENT_3D('',#1417,#1418,#1419);
#1421=CIRCLE('',#1420,5.);
#1422=CARTESIAN_POINT('',(-5.,0.,12.));
#1423=VERTEX_POINT('',#1422);
#1424=EDGE_CURVE('E480',#1423,#1423,#1421,.T.);
#1425=ORIENTED_EDGE('',*,*,#1424,.F.);
#1426=EDGE_LOOP('',(#1425));
#1427=FACE_BOUND('',#1426,.T.);
#1428=ORIENTED_EDGE('',*,*,#743,.T.);
#1429=EDGE_LOOP('',(#1428));
#1430=FACE_BOUND('',#1429,.T.);
#1431=ADVANCED_FACE('F706',(#1427,#1430),#1416,.F.);
#1432=CARTESIAN_POINT('',(0.,0.,12.));
#1433=DIRECTION('',(0.,0.,-1.));
#1434=DIRECTION('',(-1.,0.,0.));
#1435=AXIS2_PLACEMENT_3D('',#1432,#1433,#1434);
#1436=PLANE('',#1435);
#1437=ORIENTED_EDGE('',*,*,#1424,.T.);
#1438=EDGE_LOOP('',(#1437));
#1439=FACE_BOUND('',#1438,.T.);
#1440=ADVANCED_FACE('F708',(#1439),#1436,.T.);
#1441=CLOSED_SHELL('',(#289,#393,#482,#514,#536,#640,#719,#747,#767,#787,#807,#827,#1081,#1147,
#1169,#1232,#1251,#1268,#1282,#1301,#1318,#1332,#1351,#1368,#1382,#1402,#1411,#1431,#1440));
#1442=MANIFOLD_SOLID_BREP('B1',#1441);
#1443=ADVANCED_BREP_SHAPE_REPRESENTATION('',(#18,#1442),#14);
#1444=SHAPE_DEFINITION_REPRESENTATION(#9,#1443);
ENDSEC;
END-ISO-10303-21;
